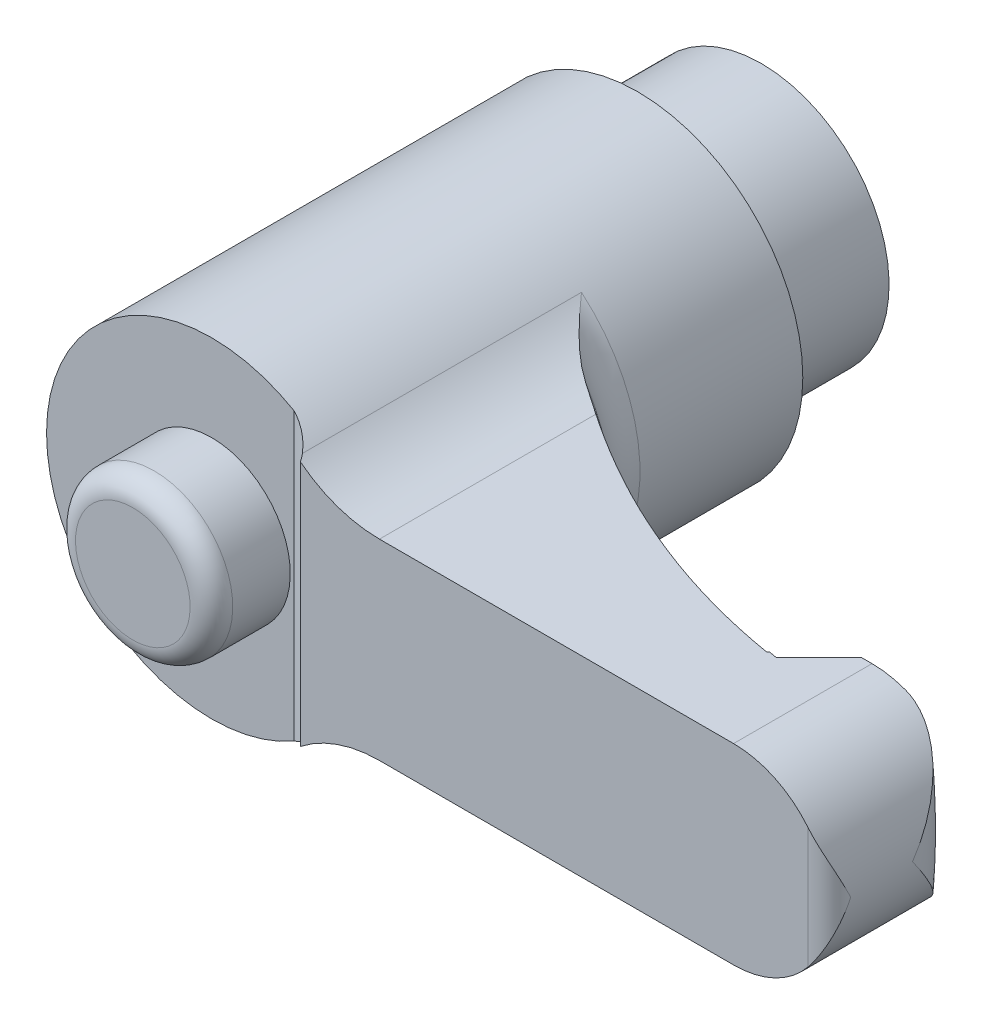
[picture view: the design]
ISO-10303-21;
HEADER;
FILE_DESCRIPTION(('STEP AP214'),'2;1');
FILE_NAME('part.step','',(''),(''),'','','');
FILE_SCHEMA(('AUTOMOTIVE_DESIGN { 1 0 10303 214 1 1 1 1 }'));
ENDSEC;
DATA;
#1=APPLICATION_CONTEXT('core data for automotive mechanical design processes');
#2=APPLICATION_PROTOCOL_DEFINITION('international standard','automotive_design',2000,#1);
#3=PRODUCT_CONTEXT('',#1,'mechanical');
#4=PRODUCT('Part','Part','',(#3));
#5=PRODUCT_RELATED_PRODUCT_CATEGORY('part','',(#4));
#6=PRODUCT_DEFINITION_FORMATION('','',#4);
#7=PRODUCT_DEFINITION_CONTEXT('part definition',#1,'design');
#8=PRODUCT_DEFINITION('design','',#6,#7);
#9=PRODUCT_DEFINITION_SHAPE('','',#8);
#10=(LENGTH_UNIT() NAMED_UNIT(*) SI_UNIT(.MILLI.,.METRE.));
#11=(NAMED_UNIT(*) PLANE_ANGLE_UNIT() SI_UNIT($,.RADIAN.));
#12=(NAMED_UNIT(*) SI_UNIT($,.STERADIAN.) SOLID_ANGLE_UNIT());
#13=UNCERTAINTY_MEASURE_WITH_UNIT(LENGTH_MEASURE(1.E-05),#10,'distance_accuracy_value','');
#14=(GEOMETRIC_REPRESENTATION_CONTEXT(3) GLOBAL_UNCERTAINTY_ASSIGNED_CONTEXT((#13)) GLOBAL_UNIT_ASSIGNED_CONTEXT((#10,
#11,#12)) REPRESENTATION_CONTEXT('',''));
#15=CARTESIAN_POINT('',(0.,0.,0.));
#16=DIRECTION('',(0.,0.,1.));
#17=DIRECTION('',(1.,0.,0.));
#18=AXIS2_PLACEMENT_3D('',#15,#16,#17);
#19=CARTESIAN_POINT('',(4.8,0.,0.));
#20=DIRECTION('',(0.,0.,1.));
#21=DIRECTION('',(0.,-1.,0.));
#22=AXIS2_PLACEMENT_3D('',#19,#20,#21);
#23=PLANE('',#22);
#24=CARTESIAN_POINT('',(0.,0.,0.));
#25=DIRECTION('',(0.,0.,-1.));
#26=DIRECTION('',(0.,1.,0.));
#27=AXIS2_PLACEMENT_3D('',#24,#25,#26);
#28=CIRCLE('',#27,2.);
#29=CARTESIAN_POINT('',(0.,2.,0.));
#30=VERTEX_POINT('',#29);
#31=EDGE_CURVE('E488',#30,#30,#28,.T.);
#32=ORIENTED_EDGE('',*,*,#31,.F.);
#33=EDGE_LOOP('',(#32));
#34=FACE_BOUND('',#33,.T.);
#35=CARTESIAN_POINT('',(0.,0.,0.));
#36=DIRECTION('',(0.,0.,-1.));
#37=DIRECTION('',(0.,1.,0.));
#38=AXIS2_PLACEMENT_3D('',#35,#36,#37);
#39=CIRCLE('',#38,4.8);
#40=CARTESIAN_POINT('',(0.,4.8,0.));
#41=VERTEX_POINT('',#40);
#42=EDGE_CURVE('E427',#41,#41,#39,.T.);
#43=ORIENTED_EDGE('',*,*,#42,.T.);
#44=EDGE_LOOP('',(#43));
#45=FACE_BOUND('',#44,.T.);
#46=ADVANCED_FACE('F14',(#34,#45),#23,.F.);
#47=CARTESIAN_POINT('',(0.,0.,26.));
#48=DIRECTION('',(0.,0.,-1.));
#49=DIRECTION('',(0.,1.,0.));
#50=AXIS2_PLACEMENT_3D('',#47,#48,#49);
#51=PLANE('',#50);
#52=CARTESIAN_POINT('',(0.,0.,26.));
#53=DIRECTION('',(0.,0.,-1.));
#54=DIRECTION('',(0.,1.,0.));
#55=AXIS2_PLACEMENT_3D('',#52,#53,#54);
#56=CIRCLE('',#55,7.75);
#57=CARTESIAN_POINT('',(3.875,-6.7116968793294,26.));
#58=VERTEX_POINT('',#57);
#59=CARTESIAN_POINT('',(3.875,6.7116968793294,26.));
#60=VERTEX_POINT('',#59);
#61=EDGE_CURVE('E374',#58,#60,#56,.T.);
#62=ORIENTED_EDGE('',*,*,#61,.F.);
#63=DIRECTION('',(0.,1.,0.));
#64=VECTOR('',#63,1.);
#65=CARTESIAN_POINT('',(3.875,-9.,26.));
#66=LINE('',#65,#64);
#67=EDGE_CURVE('E461',#58,#60,#66,.T.);
#68=ORIENTED_EDGE('',*,*,#67,.T.);
#69=EDGE_LOOP('',(#62,#68));
#70=FACE_BOUND('',#69,.T.);
#71=CARTESIAN_POINT('',(0.,0.,26.));
#72=DIRECTION('',(0.,0.,-1.));
#73=DIRECTION('',(0.,1.,0.));
#74=AXIS2_PLACEMENT_3D('',#71,#72,#73);
#75=CIRCLE('',#74,3.69047619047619);
#76=CARTESIAN_POINT('',(0.,3.69047619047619,26.));
#77=VERTEX_POINT('',#76);
#78=EDGE_CURVE('E9',#77,#77,#75,.F.);
#79=ORIENTED_EDGE('',*,*,#78,.F.);
#80=EDGE_LOOP('',(#79));
#81=FACE_BOUND('',#80,.T.);
#82=ADVANCED_FACE('F16',(#70,#81),#51,.F.);
#83=CARTESIAN_POINT('',(25.5,0.,0.));
#84=DIRECTION('',(0.,0.,1.));
#85=DIRECTION('',(0.,-1.,0.));
#86=AXIS2_PLACEMENT_3D('',#83,#84,#85);
#87=CYLINDRICAL_SURFACE('',#86,4.5);
#88=CARTESIAN_POINT('',(30.,0.,23.1));
#89=CARTESIAN_POINT('',(30.0000000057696,-0.00397224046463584,23.0972162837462));
#90=CARTESIAN_POINT('',(29.9999947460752,-0.00794462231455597,23.0944324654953));
#91=CARTESIAN_POINT('',(29.9991779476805,-0.316207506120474,22.8784039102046));
#92=CARTESIAN_POINT('',(29.967472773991,-0.621260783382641,22.6646232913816));
#93=CARTESIAN_POINT('',(29.8729566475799,-1.07288244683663,22.3499400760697));
#94=CARTESIAN_POINT('',(29.8335087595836,-1.2227001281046,22.2458576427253));
#95=CARTESIAN_POINT('',(29.7386099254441,-1.51933949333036,22.0407893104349));
#96=CARTESIAN_POINT('',(29.6831664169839,-1.6661625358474,21.9398019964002));
#97=CARTESIAN_POINT('',(29.5225221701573,-2.0316181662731,21.690355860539));
#98=CARTESIAN_POINT('',(29.4064726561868,-2.24755940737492,21.5447545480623));
#99=CARTESIAN_POINT('',(29.1349908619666,-2.66429651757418,21.2699985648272));
#100=CARTESIAN_POINT('',(28.9796468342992,-2.86512503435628,21.1408080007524));
#101=CARTESIAN_POINT('',(28.6740094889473,-3.19567948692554,20.9378778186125));
#102=CARTESIAN_POINT('',(28.5328529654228,-3.3303385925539,20.8584463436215));
#103=CARTESIAN_POINT('',(28.2285136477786,-3.58389708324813,20.7186599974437));
#104=CARTESIAN_POINT('',(28.0653563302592,-3.70281438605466,20.6582833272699));
#105=CARTESIAN_POINT('',(27.7569268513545,-3.89637158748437,20.5739705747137));
#106=CARTESIAN_POINT('',(27.6155988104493,-3.97499958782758,20.5449430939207));
#107=CARTESIAN_POINT('',(27.3962983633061,-4.08175109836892,20.516319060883));
#108=CARTESIAN_POINT('',(27.3219652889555,-4.11547521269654,20.5092639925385));
#109=CARTESIAN_POINT('',(27.1713145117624,-4.17892025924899,20.5006475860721));
#110=CARTESIAN_POINT('',(27.0949977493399,-4.20864304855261,20.4990836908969));
#111=CARTESIAN_POINT('',(26.940135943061,-4.26413478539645,20.5019689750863));
#112=CARTESIAN_POINT('',(26.8615759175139,-4.28985895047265,20.5064814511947));
#113=CARTESIAN_POINT('',(26.7037978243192,-4.33677756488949,20.5220962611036));
#114=CARTESIAN_POINT('',(26.624580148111,-4.35797453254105,20.5331949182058));
#115=CARTESIAN_POINT('',(26.4663684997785,-4.39576374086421,20.5623470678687));
#116=CARTESIAN_POINT('',(26.3873744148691,-4.41235899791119,20.5803959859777));
#117=CARTESIAN_POINT('',(26.230581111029,-4.44101436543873,20.6236628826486));
#118=CARTESIAN_POINT('',(26.1527814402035,-4.4530762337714,20.6488780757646));
#119=CARTESIAN_POINT('',(25.9747863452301,-4.47604389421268,20.7158088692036));
#120=CARTESIAN_POINT('',(25.8753706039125,-4.48535121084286,20.7602222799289));
#121=CARTESIAN_POINT('',(25.7308199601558,-4.4943380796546,20.836059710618));
#122=CARTESIAN_POINT('',(25.6833620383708,-4.49650441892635,20.8629005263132));
#123=CARTESIAN_POINT('',(25.5902043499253,-4.4993369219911,20.9195771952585));
#124=CARTESIAN_POINT('',(25.5445050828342,-4.50000266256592,20.9494138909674));
#125=CARTESIAN_POINT('',(25.4998,-4.49999999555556,20.980704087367));
#126=B_SPLINE_CURVE_WITH_KNOTS('',3,(#88,#89,#90,#91,#92,#93,#94,#95,#96,#97,#98,#99,#100,#101,
#102,#103,#104,#105,#106,#107,#108,#109,#110,#111,#112,#113,#114,#115,#116,#117,#118,#119,#120,
#121,#122,#123,#124,#125),.UNSPECIFIED.,.F.,.F.,(4,2,2,2,2,2,2,2,2,2,2,2,2,2,2,2,2,2,4),(0.,
0.0145521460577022,1.12923174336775,1.68863416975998,2.24777690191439,3.0999476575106,
3.95022123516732,4.58000022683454,5.20905610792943,5.69992949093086,5.94545977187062,
6.19087570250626,6.43886797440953,6.68672193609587,6.93441304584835,7.18200801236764,
7.50864895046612,7.67223429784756,7.83586577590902),.UNSPECIFIED.);
#127=CARTESIAN_POINT('',(27.0737254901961,-4.21584962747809,20.5));
#128=VERTEX_POINT('',#127);
#129=CARTESIAN_POINT('',(30.,0.,23.1));
#130=VERTEX_POINT('',#129);
#131=EDGE_CURVE('E133',#128,#130,#126,.F.);
#132=ORIENTED_EDGE('',*,*,#131,.T.);
#133=CARTESIAN_POINT('',(30.,0.,23.1));
#134=CARTESIAN_POINT('',(30.0000000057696,0.00397224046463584,23.0972162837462));
#135=CARTESIAN_POINT('',(29.9999947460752,0.00794462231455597,23.0944324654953));
#136=CARTESIAN_POINT('',(29.9991779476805,0.316207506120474,22.8784039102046));
#137=CARTESIAN_POINT('',(29.967472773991,0.621260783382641,22.6646232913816));
#138=CARTESIAN_POINT('',(29.8729566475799,1.07288244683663,22.3499400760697));
#139=CARTESIAN_POINT('',(29.8335087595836,1.2227001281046,22.2458576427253));
#140=CARTESIAN_POINT('',(29.7386099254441,1.51933949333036,22.0407893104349));
#141=CARTESIAN_POINT('',(29.6831664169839,1.6661625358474,21.9398019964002));
#142=CARTESIAN_POINT('',(29.5225221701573,2.0316181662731,21.690355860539));
#143=CARTESIAN_POINT('',(29.4064726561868,2.24755940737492,21.5447545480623));
#144=CARTESIAN_POINT('',(29.1349908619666,2.66429651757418,21.2699985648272));
#145=CARTESIAN_POINT('',(28.9796468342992,2.86512503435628,21.1408080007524));
#146=CARTESIAN_POINT('',(28.6740094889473,3.19567948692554,20.9378778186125));
#147=CARTESIAN_POINT('',(28.5328529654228,3.3303385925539,20.8584463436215));
#148=CARTESIAN_POINT('',(28.2285136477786,3.58389708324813,20.7186599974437));
#149=CARTESIAN_POINT('',(28.0653563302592,3.70281438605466,20.6582833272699));
#150=CARTESIAN_POINT('',(27.7569268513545,3.89637158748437,20.5739705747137));
#151=CARTESIAN_POINT('',(27.6155988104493,3.97499958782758,20.5449430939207));
#152=CARTESIAN_POINT('',(27.3962983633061,4.08175109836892,20.516319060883));
#153=CARTESIAN_POINT('',(27.3219652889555,4.11547521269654,20.5092639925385));
#154=CARTESIAN_POINT('',(27.1713145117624,4.17892025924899,20.5006475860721));
#155=CARTESIAN_POINT('',(27.0949977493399,4.20864304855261,20.4990836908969));
#156=CARTESIAN_POINT('',(26.940135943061,4.26413478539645,20.5019689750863));
#157=CARTESIAN_POINT('',(26.8615759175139,4.28985895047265,20.5064814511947));
#158=CARTESIAN_POINT('',(26.7037978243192,4.33677756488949,20.5220962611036));
#159=CARTESIAN_POINT('',(26.624580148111,4.35797453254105,20.5331949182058));
#160=CARTESIAN_POINT('',(26.4663684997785,4.39576374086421,20.5623470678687));
#161=CARTESIAN_POINT('',(26.3873744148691,4.41235899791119,20.5803959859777));
#162=CARTESIAN_POINT('',(26.230581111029,4.44101436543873,20.6236628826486));
#163=CARTESIAN_POINT('',(26.1527814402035,4.4530762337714,20.6488780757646));
#164=CARTESIAN_POINT('',(25.9747863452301,4.47604389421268,20.7158088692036));
#165=CARTESIAN_POINT('',(25.8753706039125,4.48535121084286,20.7602222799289));
#166=CARTESIAN_POINT('',(25.7308199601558,4.4943380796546,20.836059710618));
#167=CARTESIAN_POINT('',(25.6833620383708,4.49650441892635,20.8629005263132));
#168=CARTESIAN_POINT('',(25.5902043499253,4.4993369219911,20.9195771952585));
#169=CARTESIAN_POINT('',(25.5445050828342,4.50000266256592,20.9494138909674));
#170=CARTESIAN_POINT('',(25.4998,4.49999999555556,20.980704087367));
#171=B_SPLINE_CURVE_WITH_KNOTS('',3,(#133,#134,#135,#136,#137,#138,#139,#140,#141,#142,#143,
#144,#145,#146,#147,#148,#149,#150,#151,#152,#153,#154,#155,#156,#157,#158,#159,#160,#161,#162,
#163,#164,#165,#166,#167,#168,#169,#170),.UNSPECIFIED.,.F.,.F.,(4,2,2,2,2,2,2,2,2,2,2,2,2,2,2,2,
2,2,4),(0.,0.0145521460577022,1.12923174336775,1.68863416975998,2.24777690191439,
3.0999476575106,3.95022123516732,4.58000022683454,5.20905610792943,5.69992949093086,
5.94545977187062,6.19087570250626,6.43886797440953,6.68672193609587,6.93441304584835,
7.18200801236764,7.50864895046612,7.67223429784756,7.83586577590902),.UNSPECIFIED.);
#172=CARTESIAN_POINT('',(27.0737254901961,4.21584962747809,20.5));
#173=VERTEX_POINT('',#172);
#174=EDGE_CURVE('E130',#130,#173,#171,.T.);
#175=ORIENTED_EDGE('',*,*,#174,.T.);
#176=CARTESIAN_POINT('',(25.5,0.,20.5));
#177=DIRECTION('',(0.,0.,-1.));
#178=DIRECTION('',(0.,1.,0.));
#179=AXIS2_PLACEMENT_3D('',#176,#177,#178);
#180=CIRCLE('',#179,4.5);
#181=CARTESIAN_POINT('',(25.5,4.5,20.5));
#182=VERTEX_POINT('',#181);
#183=EDGE_CURVE('E399',#173,#182,#180,.F.);
#184=ORIENTED_EDGE('',*,*,#183,.T.);
#185=DIRECTION('',(0.,0.,1.));
#186=VECTOR('',#185,1.);
#187=CARTESIAN_POINT('',(25.5,4.5,0.));
#188=LINE('',#187,#186);
#189=CARTESIAN_POINT('',(25.5,4.5,27.));
#190=VERTEX_POINT('',#189);
#191=EDGE_CURVE('E398',#182,#190,#188,.T.);
#192=ORIENTED_EDGE('',*,*,#191,.T.);
#193=CARTESIAN_POINT('',(25.5,0.,27.));
#194=DIRECTION('',(0.,0.,1.));
#195=DIRECTION('',(0.,-1.,0.));
#196=AXIS2_PLACEMENT_3D('',#193,#194,#195);
#197=CIRCLE('',#196,4.5);
#198=CARTESIAN_POINT('',(29.,2.82842712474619,27.));
#199=VERTEX_POINT('',#198);
#200=EDGE_CURVE('E377',#199,#190,#197,.T.);
#201=ORIENTED_EDGE('',*,*,#200,.F.);
#202=CARTESIAN_POINT('',(29.,2.82842712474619,27.));
#203=CARTESIAN_POINT('',(29.0452569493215,2.77244060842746,26.9999705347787));
#204=CARTESIAN_POINT('',(29.08910814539,2.71541373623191,26.9969310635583));
#205=CARTESIAN_POINT('',(29.1737346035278,2.59976408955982,26.9857221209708));
#206=CARTESIAN_POINT('',(29.2145155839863,2.54114457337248,26.9775624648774));
#207=CARTESIAN_POINT('',(29.2926216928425,2.42301598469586,26.9570723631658));
#208=CARTESIAN_POINT('',(29.3299701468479,2.36351669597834,26.9447732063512));
#209=CARTESIAN_POINT('',(29.4015263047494,2.24343051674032,26.9166544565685));
#210=CARTESIAN_POINT('',(29.4357319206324,2.18284293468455,26.9008325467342));
#211=CARTESIAN_POINT('',(29.5205149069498,2.0242761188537,26.8558925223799));
#212=CARTESIAN_POINT('',(29.5686353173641,1.92562477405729,26.8244847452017));
#213=CARTESIAN_POINT('',(29.6569408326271,1.7267576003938,26.7560098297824));
#214=CARTESIAN_POINT('',(29.6971228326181,1.62654117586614,26.7189404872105));
#215=CARTESIAN_POINT('',(29.769924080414,1.42454335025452,26.6403878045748));
#216=CARTESIAN_POINT('',(29.8025090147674,1.32275698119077,26.5988856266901));
#217=CARTESIAN_POINT('',(29.8600923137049,1.1184186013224,26.5127603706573));
#218=CARTESIAN_POINT('',(29.8850925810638,1.0158667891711,26.4681380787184));
#219=CARTESIAN_POINT('',(29.9373931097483,0.763467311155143,26.3559210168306));
#220=CARTESIAN_POINT('',(29.9605764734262,0.613303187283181,26.2871011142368));
#221=CARTESIAN_POINT('',(29.9916507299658,0.312779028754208,26.1474204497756));
#222=CARTESIAN_POINT('',(29.999578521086,0.162420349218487,26.0765650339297));
#223=CARTESIAN_POINT('',(29.9999945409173,0.00809034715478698,26.0038138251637));
#224=CARTESIAN_POINT('',(29.999999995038,0.00404514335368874,26.0019068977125));
#225=CARTESIAN_POINT('',(30.,0.,26.));
#226=B_SPLINE_CURVE_WITH_KNOTS('',3,(#202,#203,#204,#205,#206,#207,#208,#209,#210,#211,#212,
#213,#214,#215,#216,#217,#218,#219,#220,#221,#222,#223,#224,#225),.UNSPECIFIED.,.F.,.F.,(4,2,2,
2,2,2,2,2,2,2,2,4),(0.,0.215782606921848,0.431152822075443,0.644930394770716,0.858848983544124,
1.20082332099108,1.5429311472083,1.88655545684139,2.23009348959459,2.7297347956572,
3.22816610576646,3.2415825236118),.UNSPECIFIED.);
#227=CARTESIAN_POINT('',(30.,0.,26.));
#228=VERTEX_POINT('',#227);
#229=EDGE_CURVE('E173',#228,#199,#226,.F.);
#230=ORIENTED_EDGE('',*,*,#229,.F.);
#231=CARTESIAN_POINT('',(29.,-2.82842712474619,27.));
#232=CARTESIAN_POINT('',(29.0452569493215,-2.77244060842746,26.9999705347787));
#233=CARTESIAN_POINT('',(29.08910814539,-2.71541373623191,26.9969310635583));
#234=CARTESIAN_POINT('',(29.1737346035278,-2.59976408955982,26.9857221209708));
#235=CARTESIAN_POINT('',(29.2145155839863,-2.54114457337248,26.9775624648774));
#236=CARTESIAN_POINT('',(29.2926216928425,-2.42301598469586,26.9570723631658));
#237=CARTESIAN_POINT('',(29.3299701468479,-2.36351669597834,26.9447732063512));
#238=CARTESIAN_POINT('',(29.4015263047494,-2.24343051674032,26.9166544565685));
#239=CARTESIAN_POINT('',(29.4357319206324,-2.18284293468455,26.9008325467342));
#240=CARTESIAN_POINT('',(29.5205149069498,-2.0242761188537,26.8558925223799));
#241=CARTESIAN_POINT('',(29.5686353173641,-1.92562477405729,26.8244847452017));
#242=CARTESIAN_POINT('',(29.6569408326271,-1.7267576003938,26.7560098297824));
#243=CARTESIAN_POINT('',(29.6971228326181,-1.62654117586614,26.7189404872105));
#244=CARTESIAN_POINT('',(29.769924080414,-1.42454335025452,26.6403878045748));
#245=CARTESIAN_POINT('',(29.8025090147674,-1.32275698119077,26.5988856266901));
#246=CARTESIAN_POINT('',(29.8600923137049,-1.1184186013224,26.5127603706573));
#247=CARTESIAN_POINT('',(29.8850925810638,-1.0158667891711,26.4681380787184));
#248=CARTESIAN_POINT('',(29.9373931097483,-0.763467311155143,26.3559210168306));
#249=CARTESIAN_POINT('',(29.9605764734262,-0.613303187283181,26.2871011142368));
#250=CARTESIAN_POINT('',(29.9916507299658,-0.312779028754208,26.1474204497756));
#251=CARTESIAN_POINT('',(29.999578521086,-0.162420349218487,26.0765650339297));
#252=CARTESIAN_POINT('',(29.9999945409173,-0.00809034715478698,26.0038138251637));
#253=CARTESIAN_POINT('',(29.999999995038,-0.00404514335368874,26.0019068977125));
#254=CARTESIAN_POINT('',(30.,0.,26.));
#255=B_SPLINE_CURVE_WITH_KNOTS('',3,(#231,#232,#233,#234,#235,#236,#237,#238,#239,#240,#241,
#242,#243,#244,#245,#246,#247,#248,#249,#250,#251,#252,#253,#254),.UNSPECIFIED.,.F.,.F.,(4,2,2,
2,2,2,2,2,2,2,2,4),(0.,0.215782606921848,0.431152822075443,0.644930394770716,0.858848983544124,
1.20082332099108,1.5429311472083,1.88655545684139,2.23009348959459,2.7297347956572,
3.22816610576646,3.2415825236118),.UNSPECIFIED.);
#256=CARTESIAN_POINT('',(29.,-2.82842712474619,27.));
#257=VERTEX_POINT('',#256);
#258=EDGE_CURVE('E22',#257,#228,#255,.T.);
#259=ORIENTED_EDGE('',*,*,#258,.F.);
#260=CARTESIAN_POINT('',(25.5,-4.5,27.));
#261=VERTEX_POINT('',#260);
#262=EDGE_CURVE('E383',#261,#257,#197,.T.);
#263=ORIENTED_EDGE('',*,*,#262,.F.);
#264=DIRECTION('',(0.,0.,1.));
#265=VECTOR('',#264,1.);
#266=CARTESIAN_POINT('',(25.5,-4.5,0.));
#267=LINE('',#266,#265);
#268=CARTESIAN_POINT('',(25.5,-4.5,20.5));
#269=VERTEX_POINT('',#268);
#270=EDGE_CURVE('E403',#269,#261,#267,.T.);
#271=ORIENTED_EDGE('',*,*,#270,.F.);
#272=EDGE_CURVE('E140',#269,#128,#180,.F.);
#273=ORIENTED_EDGE('',*,*,#272,.T.);
#274=EDGE_LOOP('',(#132,#175,#184,#192,#201,#230,#259,#263,#271,#273));
#275=FACE_BOUND('',#274,.T.);
#276=ADVANCED_FACE('F138',(#275),#87,.T.);
#277=CARTESIAN_POINT('',(28.072410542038,-9.,-7.06806810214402));
#278=DIRECTION('',(0.,1.,0.));
#279=DIRECTION('',(-1.,0.,0.));
#280=AXIS2_PLACEMENT_3D('',#277,#278,#279);
#281=CYLINDRICAL_SURFACE('',#280,30.);
#282=CARTESIAN_POINT('',(22.457864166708,5.40076351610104,22.4018635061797));
#283=CARTESIAN_POINT('',(22.5328704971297,5.02783315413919,22.4161416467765));
#284=CARTESIAN_POINT('',(22.6003478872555,4.65331694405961,22.4287120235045));
#285=CARTESIAN_POINT('',(22.7199001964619,3.90172149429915,22.4506465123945));
#286=CARTESIAN_POINT('',(22.7719742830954,3.52464211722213,22.4600104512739));
#287=CARTESIAN_POINT('',(22.860391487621,2.76836181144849,22.4757441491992));
#288=CARTESIAN_POINT('',(22.8967259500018,2.38915983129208,22.4821122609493));
#289=CARTESIAN_POINT('',(22.953399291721,1.62955869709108,22.4919810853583));
#290=CARTESIAN_POINT('',(22.9737386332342,1.24915957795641,22.4954818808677));
#291=CARTESIAN_POINT('',(23.0101209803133,0.119914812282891,22.5017516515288));
#292=CARTESIAN_POINT('',(23.0030278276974,-0.62982701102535,22.5005458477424));
#293=CARTESIAN_POINT('',(22.9265280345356,-2.12549757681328,22.487326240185));
#294=CARTESIAN_POINT('',(22.8571649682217,-2.87142861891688,22.4753199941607));
#295=CARTESIAN_POINT('',(22.717445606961,-3.91200869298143,22.450161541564));
#296=CARTESIAN_POINT('',(22.6723784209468,-4.21035002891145,22.4419679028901));
#297=CARTESIAN_POINT('',(22.5724363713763,-4.80637536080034,22.4235048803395));
#298=CARTESIAN_POINT('',(22.5175283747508,-5.10405358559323,22.4132284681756));
#299=CARTESIAN_POINT('',(22.457864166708,-5.40076351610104,22.4018635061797));
#300=B_SPLINE_CURVE_WITH_KNOTS('',3,(#282,#283,#284,#285,#286,#287,#288,#289,#290,#291,#292,
#293,#294,#295,#296,#297,#298,#299),.UNSPECIFIED.,.F.,.F.,(4,2,2,2,2,2,2,2,4),(0.,
1.14192528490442,2.28391227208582,3.4265264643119,4.56910763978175,6.81558260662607,
9.06048679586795,9.96586555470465,10.8743519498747),.UNSPECIFIED.);
#301=CARTESIAN_POINT('',(23.,0.,22.5));
#302=VERTEX_POINT('',#301);
#303=CARTESIAN_POINT('',(22.6238084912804,-4.5,22.4329951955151));
#304=VERTEX_POINT('',#303);
#305=EDGE_CURVE('E136',#302,#304,#300,.T.);
#306=ORIENTED_EDGE('',*,*,#305,.F.);
#307=DIRECTION('',(0.,1.,0.));
#308=VECTOR('',#307,1.);
#309=CARTESIAN_POINT('',(23.,-9.,22.5));
#310=LINE('',#309,#308);
#311=CARTESIAN_POINT('',(23.,-4.5,22.5));
#312=VERTEX_POINT('',#311);
#313=EDGE_CURVE('E467',#312,#302,#310,.T.);
#314=ORIENTED_EDGE('',*,*,#313,.F.);
#315=CARTESIAN_POINT('',(28.072410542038,-4.5,-7.06806810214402));
#316=DIRECTION('',(0.,1.,0.));
#317=DIRECTION('',(-1.,0.,0.));
#318=AXIS2_PLACEMENT_3D('',#315,#316,#317);
#319=CIRCLE('',#318,30.);
#320=EDGE_CURVE('E458',#312,#304,#319,.F.);
#321=ORIENTED_EDGE('',*,*,#320,.T.);
#322=EDGE_LOOP('',(#306,#314,#321));
#323=FACE_BOUND('',#322,.T.);
#324=ADVANCED_FACE('F162',(#323),#281,.F.);
#325=CARTESIAN_POINT('',(27.4,-9.,20.5));
#326=DIRECTION('',(0.,0.,-1.));
#327=DIRECTION('',(0.,1.,0.));
#328=AXIS2_PLACEMENT_3D('',#325,#326,#327);
#329=PLANE('',#328);
#330=ORIENTED_EDGE('',*,*,#183,.F.);
#331=CARTESIAN_POINT('',(0.,0.,20.5));
#332=DIRECTION('',(0.,0.,-1.));
#333=DIRECTION('',(0.,1.,0.));
#334=AXIS2_PLACEMENT_3D('',#331,#332,#333);
#335=CIRCLE('',#334,27.4);
#336=EDGE_CURVE('E37',#173,#128,#335,.T.);
#337=ORIENTED_EDGE('',*,*,#336,.T.);
#338=ORIENTED_EDGE('',*,*,#272,.F.);
#339=DIRECTION('',(-1.,0.,0.));
#340=VECTOR('',#339,1.);
#341=CARTESIAN_POINT('',(25.5,-4.5,20.5));
#342=LINE('',#341,#340);
#343=CARTESIAN_POINT('',(25.,-4.5,20.5));
#344=VERTEX_POINT('',#343);
#345=EDGE_CURVE('E538',#269,#344,#342,.T.);
#346=ORIENTED_EDGE('',*,*,#345,.T.);
#347=DIRECTION('',(0.,1.,0.));
#348=VECTOR('',#347,1.);
#349=CARTESIAN_POINT('',(25.,-9.,20.5));
#350=LINE('',#349,#348);
#351=CARTESIAN_POINT('',(25.,4.5,20.5));
#352=VERTEX_POINT('',#351);
#353=EDGE_CURVE('E454',#344,#352,#350,.T.);
#354=ORIENTED_EDGE('',*,*,#353,.T.);
#355=DIRECTION('',(1.,0.,0.));
#356=VECTOR('',#355,1.);
#357=CARTESIAN_POINT('',(8.87764045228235,4.5,20.5));
#358=LINE('',#357,#356);
#359=EDGE_CURVE('E413',#352,#182,#358,.T.);
#360=ORIENTED_EDGE('',*,*,#359,.T.);
#361=EDGE_LOOP('',(#330,#337,#338,#346,#354,#360));
#362=FACE_BOUND('',#361,.T.);
#363=ADVANCED_FACE('F191',(#362),#329,.T.);
#364=CARTESIAN_POINT('',(0.,0.,27.));
#365=DIRECTION('',(0.,0.,1.));
#366=DIRECTION('',(0.,-1.,0.));
#367=AXIS2_PLACEMENT_3D('',#364,#365,#366);
#368=PLANE('',#367);
#369=CARTESIAN_POINT('',(8.87764045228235,10.5,27.));
#370=DIRECTION('',(0.,0.,1.));
#371=DIRECTION('',(1.,0.,0.));
#372=AXIS2_PLACEMENT_3D('',#369,#370,#371);
#373=CIRCLE('',#372,6.);
#374=CARTESIAN_POINT('',(5.16666666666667,5.78527057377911,27.));
#375=VERTEX_POINT('',#374);
#376=CARTESIAN_POINT('',(8.87764045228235,4.5,27.));
#377=VERTEX_POINT('',#376);
#378=EDGE_CURVE('E408',#375,#377,#373,.T.);
#379=ORIENTED_EDGE('',*,*,#378,.F.);
#380=DIRECTION('',(0.,1.,0.));
#381=VECTOR('',#380,1.);
#382=CARTESIAN_POINT('',(5.16666666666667,-9.,27.));
#383=LINE('',#382,#381);
#384=CARTESIAN_POINT('',(5.16666666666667,-5.78527057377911,27.));
#385=VERTEX_POINT('',#384);
#386=EDGE_CURVE('E447',#385,#375,#383,.T.);
#387=ORIENTED_EDGE('',*,*,#386,.F.);
#388=CARTESIAN_POINT('',(8.87764045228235,-10.5,27.));
#389=DIRECTION('',(0.,0.,1.));
#390=DIRECTION('',(1.,0.,0.));
#391=AXIS2_PLACEMENT_3D('',#388,#389,#390);
#392=CIRCLE('',#391,6.);
#393=CARTESIAN_POINT('',(8.87764045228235,-4.5,27.));
#394=VERTEX_POINT('',#393);
#395=EDGE_CURVE('E411',#394,#385,#392,.T.);
#396=ORIENTED_EDGE('',*,*,#395,.F.);
#397=DIRECTION('',(-1.,0.,0.));
#398=VECTOR('',#397,1.);
#399=CARTESIAN_POINT('',(25.5,-4.5,27.));
#400=LINE('',#399,#398);
#401=EDGE_CURVE('E407',#261,#394,#400,.T.);
#402=ORIENTED_EDGE('',*,*,#401,.F.);
#403=ORIENTED_EDGE('',*,*,#262,.T.);
#404=DIRECTION('',(0.,1.,0.));
#405=VECTOR('',#404,1.);
#406=CARTESIAN_POINT('',(29.,-9.,27.));
#407=LINE('',#406,#405);
#408=EDGE_CURVE('E395',#257,#199,#407,.T.);
#409=ORIENTED_EDGE('',*,*,#408,.T.);
#410=ORIENTED_EDGE('',*,*,#200,.T.);
#411=DIRECTION('',(1.,0.,0.));
#412=VECTOR('',#411,1.);
#413=CARTESIAN_POINT('',(8.87764045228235,4.5,27.));
#414=LINE('',#413,#412);
#415=EDGE_CURVE('E394',#377,#190,#414,.T.);
#416=ORIENTED_EDGE('',*,*,#415,.F.);
#417=EDGE_LOOP('',(#379,#387,#396,#402,#403,#409,#410,#416));
#418=FACE_BOUND('',#417,.T.);
#419=ADVANCED_FACE('F238',(#418),#368,.T.);
#420=CARTESIAN_POINT('',(0.,0.,0.));
#421=DIRECTION('',(0.,0.,-1.));
#422=DIRECTION('',(0.,1.,0.));
#423=AXIS2_PLACEMENT_3D('',#420,#421,#422);
#424=CYLINDRICAL_SURFACE('',#423,7.75);
#425=CARTESIAN_POINT('',(0.,0.,13.6426560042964));
#426=DIRECTION('',(0.,0.,-1.));
#427=DIRECTION('',(0.,1.,0.));
#428=AXIS2_PLACEMENT_3D('',#425,#426,#427);
#429=CIRCLE('',#428,7.75);
#430=CARTESIAN_POINT('',(5.00376098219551,5.91818181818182,13.6426560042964));
#431=VERTEX_POINT('',#430);
#432=CARTESIAN_POINT('',(5.00376098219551,-5.91818181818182,13.6426560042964));
#433=VERTEX_POINT('',#432);
#434=EDGE_CURVE('E368',#431,#433,#429,.T.);
#435=ORIENTED_EDGE('',*,*,#434,.T.);
#436=DIRECTION('',(0.,0.,1.));
#437=VECTOR('',#436,1.);
#438=CARTESIAN_POINT('',(5.00376098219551,-5.91818181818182,0.));
#439=LINE('',#438,#437);
#440=CARTESIAN_POINT('',(5.00376098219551,-5.91818181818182,26.7442638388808));
#441=VERTEX_POINT('',#440);
#442=EDGE_CURVE('E419',#433,#441,#439,.T.);
#443=ORIENTED_EDGE('',*,*,#442,.T.);
#444=CARTESIAN_POINT('',(3.875,-6.7116968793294,26.));
#445=CARTESIAN_POINT('',(3.9487248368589,-6.66914880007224,26.0179048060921));
#446=CARTESIAN_POINT('',(4.02097408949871,-6.62579988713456,26.039874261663));
#447=CARTESIAN_POINT('',(4.16199829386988,-6.53812669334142,26.0915573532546));
#448=CARTESIAN_POINT('',(4.23077434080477,-6.49380272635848,26.1212685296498));
#449=CARTESIAN_POINT('',(4.36202505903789,-6.40634475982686,26.1868862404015));
#450=CARTESIAN_POINT('',(4.42463632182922,-6.36322379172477,26.2225378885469));
#451=CARTESIAN_POINT('',(4.54579687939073,-6.27724013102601,26.3004737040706));
#452=CARTESIAN_POINT('',(4.60434578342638,-6.23437746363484,26.3427585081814));
#453=CARTESIAN_POINT('',(4.71026264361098,-6.1546555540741,26.4283893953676));
#454=CARTESIAN_POINT('',(4.75813291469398,-6.11768751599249,26.4710140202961));
#455=CARTESIAN_POINT('',(4.8500303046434,-6.04509175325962,26.56120031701));
#456=CARTESIAN_POINT('',(4.89405965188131,-6.00946325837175,26.6087590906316));
#457=CARTESIAN_POINT('',(4.97925799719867,-5.9390764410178,26.7103994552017));
#458=CARTESIAN_POINT('',(5.02029084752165,-5.90438218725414,26.7646407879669));
#459=CARTESIAN_POINT('',(5.09738332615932,-5.83796295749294,26.8783962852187));
#460=CARTESIAN_POINT('',(5.13343386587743,-5.80624344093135,26.9379197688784));
#461=CARTESIAN_POINT('',(5.16666666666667,-5.77650894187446,27.));
#462=B_SPLINE_CURVE_WITH_KNOTS('',3,(#444,#445,#446,#447,#448,#449,#450,#451,#452,#453,#454,
#455,#456,#457,#458,#459,#460,#461),.UNSPECIFIED.,.F.,.F.,(4,2,2,2,2,2,2,2,4),(0.,
0.260811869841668,0.521540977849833,0.773092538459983,1.02466826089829,1.24638864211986,
1.4679795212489,1.69664297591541,1.92571819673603),.UNSPECIFIED.);
#463=EDGE_CURVE('E213',#58,#441,#462,.T.);
#464=ORIENTED_EDGE('',*,*,#463,.F.);
#465=ORIENTED_EDGE('',*,*,#61,.T.);
#466=CARTESIAN_POINT('',(5.16666666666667,5.77650894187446,27.));
#467=CARTESIAN_POINT('',(5.13714077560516,5.80292379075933,26.9448365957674));
#468=CARTESIAN_POINT('',(5.1053831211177,5.83091583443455,26.8916890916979));
#469=CARTESIAN_POINT('',(5.03785941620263,5.88934998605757,26.7895453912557));
#470=CARTESIAN_POINT('',(5.00209830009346,5.91978906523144,26.7405442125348));
#471=CARTESIAN_POINT('',(4.92700880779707,5.98243056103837,26.646752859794));
#472=CARTESIAN_POINT('',(4.88768622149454,6.01463008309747,26.6019560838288));
#473=CARTESIAN_POINT('',(4.80573825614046,6.08030777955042,26.5165060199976));
#474=CARTESIAN_POINT('',(4.76311181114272,6.11378636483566,26.4758540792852));
#475=CARTESIAN_POINT('',(4.63114473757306,6.21507952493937,26.3605779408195));
#476=CARTESIAN_POINT('',(4.53728284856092,6.28411879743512,26.2920994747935));
#477=CARTESIAN_POINT('',(4.3393749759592,6.42237347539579,26.1724069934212));
#478=CARTESIAN_POINT('',(4.23533663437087,6.49158871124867,26.1211801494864));
#479=CARTESIAN_POINT('',(4.08621326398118,6.5854168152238,26.0632790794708));
#480=CARTESIAN_POINT('',(4.04469277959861,6.61100425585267,26.0487072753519));
#481=CARTESIAN_POINT('',(3.96061680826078,6.66171281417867,26.0222973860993));
#482=CARTESIAN_POINT('',(3.91806319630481,6.68683464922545,26.0104547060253));
#483=CARTESIAN_POINT('',(3.8750000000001,6.7116968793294,26.));
#484=B_SPLINE_CURVE_WITH_KNOTS('',3,(#466,#467,#468,#469,#470,#471,#472,#473,#474,#475,#476,
#477,#478,#479,#480,#481,#482,#483),.UNSPECIFIED.,.F.,.F.,(4,2,2,2,2,2,2,2,4),(0.,
0.203583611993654,0.406919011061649,0.609929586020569,0.813005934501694,1.21684507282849,
1.62038324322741,1.77301957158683,1.9253970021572),.UNSPECIFIED.);
#485=CARTESIAN_POINT('',(5.0037609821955,5.91818181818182,26.7442638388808));
#486=VERTEX_POINT('',#485);
#487=EDGE_CURVE('E226',#486,#60,#484,.T.);
#488=ORIENTED_EDGE('',*,*,#487,.F.);
#489=DIRECTION('',(0.,0.,1.));
#490=VECTOR('',#489,1.);
#491=CARTESIAN_POINT('',(5.00376098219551,5.91818181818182,0.));
#492=LINE('',#491,#490);
#493=EDGE_CURVE('E425',#431,#486,#492,.T.);
#494=ORIENTED_EDGE('',*,*,#493,.F.);
#495=EDGE_LOOP('',(#435,#443,#464,#465,#488,#494));
#496=FACE_BOUND('',#495,.T.);
#497=CARTESIAN_POINT('',(0.,0.,6.));
#498=DIRECTION('',(0.,0.,-1.));
#499=DIRECTION('',(0.,1.,0.));
#500=AXIS2_PLACEMENT_3D('',#497,#498,#499);
#501=CIRCLE('',#500,7.75);
#502=CARTESIAN_POINT('',(0.,7.75,6.));
#503=VERTEX_POINT('',#502);
#504=EDGE_CURVE('E372',#503,#503,#501,.T.);
#505=ORIENTED_EDGE('',*,*,#504,.F.);
#506=EDGE_LOOP('',(#505));
#507=FACE_BOUND('',#506,.T.);
#508=ADVANCED_FACE('F236',(#496,#507),#424,.T.);
#509=CARTESIAN_POINT('',(8.87764045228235,10.5,0.));
#510=DIRECTION('',(0.,0.,1.));
#511=DIRECTION('',(0.,-1.,0.));
#512=AXIS2_PLACEMENT_3D('',#509,#510,#511);
#513=CYLINDRICAL_SURFACE('',#512,6.);
#514=DIRECTION('',(0.,0.,1.));
#515=VECTOR('',#514,1.);
#516=CARTESIAN_POINT('',(8.87764045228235,4.5,0.));
#517=LINE('',#516,#515);
#518=CARTESIAN_POINT('',(8.87764045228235,4.5,16.8419191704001));
#519=VERTEX_POINT('',#518);
#520=EDGE_CURVE('E402',#519,#377,#517,.T.);
#521=ORIENTED_EDGE('',*,*,#520,.F.);
#522=CARTESIAN_POINT('',(8.87784045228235,4.50000000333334,16.8420543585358));
#523=CARTESIAN_POINT('',(8.76298675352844,4.50000678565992,16.7644412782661));
#524=CARTESIAN_POINT('',(8.64795886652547,4.50329006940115,16.687069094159));
#525=CARTESIAN_POINT('',(8.41786670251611,4.51653249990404,16.5336144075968));
#526=CARTESIAN_POINT('',(8.30280331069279,4.52647413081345,16.457529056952));
#527=CARTESIAN_POINT('',(8.07233993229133,4.55315590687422,16.3070362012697));
#528=CARTESIAN_POINT('',(7.95693991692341,4.56989665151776,16.2326288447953));
#529=CARTESIAN_POINT('',(7.72548993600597,4.61048878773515,16.0861329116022));
#530=CARTESIAN_POINT('',(7.60943905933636,4.63435875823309,16.0140509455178));
#531=CARTESIAN_POINT('',(7.49320434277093,4.66190641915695,15.9436475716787));
#532=B_SPLINE_CURVE_WITH_KNOTS('',3,(#522,#523,#524,#525,#526,#527,#528,#529,#530,#531),
.UNSPECIFIED.,.F.,.F.,(4,2,2,2,4),(0.,0.415830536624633,0.830571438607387,1.24534891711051,
1.66121688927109),.UNSPECIFIED.);
#533=CARTESIAN_POINT('',(7.49353468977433,4.66182809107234,15.9438475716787));
#534=VERTEX_POINT('',#533);
#535=EDGE_CURVE('E252',#519,#534,#532,.T.);
#536=ORIENTED_EDGE('',*,*,#535,.T.);
#537=CARTESIAN_POINT('',(7.49386505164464,4.66174977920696,15.9440475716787));
#538=CARTESIAN_POINT('',(7.41534599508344,4.68036361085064,15.8965108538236));
#539=CARTESIAN_POINT('',(7.33813459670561,4.70033346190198,15.8474028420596));
#540=CARTESIAN_POINT('',(7.18628313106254,4.74278447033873,15.7464454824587));
#541=CARTESIAN_POINT('',(7.11164195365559,4.76526452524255,15.694597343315));
#542=CARTESIAN_POINT('',(6.89171782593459,4.83609524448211,15.5357042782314));
#543=CARTESIAN_POINT('',(6.75010221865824,4.88791699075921,15.4251060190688));
#544=CARTESIAN_POINT('',(6.47674906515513,4.99932791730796,15.1976148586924));
#545=CARTESIAN_POINT('',(6.34496293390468,5.05887426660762,15.0807586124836));
#546=CARTESIAN_POINT('',(6.08952700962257,5.18523508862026,14.8421034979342));
#547=CARTESIAN_POINT('',(5.96588083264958,5.25205275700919,14.7203024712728));
#548=CARTESIAN_POINT('',(5.6959472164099,5.41010140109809,14.4425118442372));
#549=CARTESIAN_POINT('',(5.55174299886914,5.50325599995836,14.2855983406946));
#550=CARTESIAN_POINT('',(5.27355500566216,5.70004368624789,13.9693256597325));
#551=CARTESIAN_POINT('',(5.13957057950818,5.80367610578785,13.8099666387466));
#552=CARTESIAN_POINT('',(5.00807252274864,5.91453907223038,13.6479722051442));
#553=CARTESIAN_POINT('',(5.00591610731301,5.91635969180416,13.6453140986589));
#554=CARTESIAN_POINT('',(5.00376098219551,5.91818181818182,13.6426560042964));
#555=B_SPLINE_CURVE_WITH_KNOTS('',3,(#537,#538,#539,#540,#541,#542,#543,#544,#545,#546,#547,
#548,#549,#550,#551,#552,#553,#554),.UNSPECIFIED.,.F.,.F.,(4,2,2,2,2,2,2,2,4),(0.,
0.280888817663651,0.561654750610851,1.12199628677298,1.67935400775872,2.2369576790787,
2.93418472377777,3.63136735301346,3.6429980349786),.UNSPECIFIED.);
#556=EDGE_CURVE('E243',#534,#431,#555,.T.);
#557=ORIENTED_EDGE('',*,*,#556,.T.);
#558=ORIENTED_EDGE('',*,*,#493,.T.);
#559=CARTESIAN_POINT('',(5.16666666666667,5.78527057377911,27.));
#560=CARTESIAN_POINT('',(5.1544362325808,5.79489712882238,26.9771411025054));
#561=CARTESIAN_POINT('',(5.14182657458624,5.80489933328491,26.9546446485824));
#562=CARTESIAN_POINT('',(5.11593353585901,5.82561925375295,26.910451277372));
#563=CARTESIAN_POINT('',(5.10265156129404,5.83633549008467,26.8887528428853));
#564=CARTESIAN_POINT('',(5.07544919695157,5.85848632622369,26.8461383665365));
#565=CARTESIAN_POINT('',(5.06152881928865,5.86992091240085,26.8252223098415));
#566=CARTESIAN_POINT('',(5.03308032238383,5.89351543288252,26.784152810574));
#567=CARTESIAN_POINT('',(5.0185510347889,5.90567678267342,26.7640009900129));
#568=CARTESIAN_POINT('',(5.0037609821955,5.91818181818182,26.7442638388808));
#569=B_SPLINE_CURVE_WITH_KNOTS('',3,(#559,#560,#561,#562,#563,#564,#565,#566,#567,#568),
.UNSPECIFIED.,.F.,.F.,(4,2,2,2,4),(0.,0.0829550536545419,0.165743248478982,0.248529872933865,
0.331483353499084),.UNSPECIFIED.);
#570=EDGE_CURVE('E220',#375,#486,#569,.T.);
#571=ORIENTED_EDGE('',*,*,#570,.F.);
#572=ORIENTED_EDGE('',*,*,#378,.T.);
#573=EDGE_LOOP('',(#521,#536,#557,#558,#571,#572));
#574=FACE_BOUND('',#573,.T.);
#575=ADVANCED_FACE('F232',(#574),#513,.F.);
#576=CARTESIAN_POINT('',(8.87764045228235,4.5,0.));
#577=DIRECTION('',(0.,-1.,0.));
#578=DIRECTION('',(1.,0.,0.));
#579=AXIS2_PLACEMENT_3D('',#576,#577,#578);
#580=PLANE('',#579);
#581=CARTESIAN_POINT('',(28.072410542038,4.5,-7.06806810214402));
#582=DIRECTION('',(0.,-1.,0.));
#583=DIRECTION('',(1.,0.,0.));
#584=AXIS2_PLACEMENT_3D('',#581,#582,#583);
#585=CIRCLE('',#584,30.);
#586=CARTESIAN_POINT('',(22.6238084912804,4.5,22.432995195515));
#587=VERTEX_POINT('',#586);
#588=CARTESIAN_POINT('',(23.,4.5,22.5));
#589=VERTEX_POINT('',#588);
#590=EDGE_CURVE('E455',#587,#589,#585,.F.);
#591=ORIENTED_EDGE('',*,*,#590,.F.);
#592=CARTESIAN_POINT('',(44.3300735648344,4.5,0.942111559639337));
#593=CARTESIAN_POINT('',(43.4547012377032,4.5,1.81300466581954));
#594=CARTESIAN_POINT('',(42.5792011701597,4.5,2.68376940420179));
#595=CARTESIAN_POINT('',(40.8278840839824,4.5,4.42498033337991));
#596=CARTESIAN_POINT('',(39.9520670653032,4.5,5.29542652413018));
#597=CARTESIAN_POINT('',(37.3240501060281,4.5,7.90619283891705));
#598=CARTESIAN_POINT('',(35.5712829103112,4.5,9.64594205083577));
#599=CARTESIAN_POINT('',(32.0635642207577,4.5,13.1230346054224));
#600=CARTESIAN_POINT('',(30.3086128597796,4.5,14.8603780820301));
#601=CARTESIAN_POINT('',(27.6733297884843,4.5,17.4635089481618));
#602=CARTESIAN_POINT('',(26.7944244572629,4.5,18.3307401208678));
#603=CARTESIAN_POINT('',(25.0353323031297,4.5,20.0639019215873));
#604=CARTESIAN_POINT('',(24.155145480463,4.5,20.9298325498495));
#605=CARTESIAN_POINT('',(22.3129521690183,4.5,22.7385304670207));
#606=CARTESIAN_POINT('',(21.3507796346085,4.5,23.6811286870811));
#607=CARTESIAN_POINT('',(19.4234130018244,4.5,25.5632155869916));
#608=CARTESIAN_POINT('',(18.4582189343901,4.5,26.5027042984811));
#609=CARTESIAN_POINT('',(17.0068469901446,4.5,27.9082821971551));
#610=CARTESIAN_POINT('',(16.5224491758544,4.5,28.3762088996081));
#611=CARTESIAN_POINT('',(15.5521170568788,4.5,29.3104634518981));
#612=CARTESIAN_POINT('',(15.0661827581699,4.5,29.7767913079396));
#613=CARTESIAN_POINT('',(14.0922926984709,4.5,30.7073654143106));
#614=CARTESIAN_POINT('',(13.6043368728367,4.5,31.1716115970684));
#615=CARTESIAN_POINT('',(12.8703741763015,4.5,31.8658425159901));
#616=CARTESIAN_POINT('',(12.625380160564,4.5,32.0968979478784));
#617=CARTESIAN_POINT('',(12.1345901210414,4.5,32.5581570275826));
#618=CARTESIAN_POINT('',(11.8887940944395,4.5,32.7883606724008));
#619=CARTESIAN_POINT('',(11.6425345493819,4.5,33.0180686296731));
#620=B_SPLINE_CURVE_WITH_KNOTS('',3,(#592,#593,#594,#595,#596,#597,#598,#599,#600,#601,#602,
#603,#604,#605,#606,#607,#608,#609,#610,#611,#612,#613,#614,#615,#616,#617,#618,#619),
.UNSPECIFIED.,.F.,.F.,(4,2,2,2,2,2,2,2,2,2,2,2,2,4),(0.,3.70440058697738,7.40880170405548,
14.8175982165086,22.225964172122,25.9301609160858,29.6343569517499,33.6751954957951,
37.7159927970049,39.736477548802,41.7569544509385,43.7774964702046,44.7877808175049,
45.7980687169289),.UNSPECIFIED.);
#621=CARTESIAN_POINT('',(22.55548713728,4.5,22.5));
#622=VERTEX_POINT('',#621);
#623=EDGE_CURVE('E298',#587,#622,#620,.T.);
#624=ORIENTED_EDGE('',*,*,#623,.T.);
#625=CARTESIAN_POINT('',(15.4388208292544,4.5,20.4312501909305));
#626=CARTESIAN_POINT('',(14.9382009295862,4.5,20.2216724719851));
#627=CARTESIAN_POINT('',(14.4426076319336,4.5,19.9999912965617));
#628=CARTESIAN_POINT('',(13.4622769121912,4.5,19.5336725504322));
#629=CARTESIAN_POINT('',(12.9775414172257,4.5,19.2890309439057));
#630=CARTESIAN_POINT('',(12.0194633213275,4.5,18.778303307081));
#631=CARTESIAN_POINT('',(11.5461217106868,4.5,18.5122154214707));
#632=CARTESIAN_POINT('',(10.6110367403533,4.5,17.9604954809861));
#633=CARTESIAN_POINT('',(10.1492927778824,4.5,17.6748644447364));
#634=CARTESIAN_POINT('',(9.23133715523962,4.5,17.0827723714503));
#635=CARTESIAN_POINT('',(8.77526312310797,4.5,16.776098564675));
#636=CARTESIAN_POINT('',(8.09865121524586,4.5,16.3053789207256));
#637=CARTESIAN_POINT('',(7.87435773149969,4.5,16.1466830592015));
#638=CARTESIAN_POINT('',(7.42793360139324,4.5,15.826278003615));
#639=CARTESIAN_POINT('',(7.20580294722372,4.5,15.6645688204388));
#640=CARTESIAN_POINT('',(6.76333109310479,4.5,15.3388557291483));
#641=CARTESIAN_POINT('',(6.54298941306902,4.5,15.1748524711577));
#642=CARTESIAN_POINT('',(6.10341304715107,4.5,14.8453678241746));
#643=CARTESIAN_POINT('',(5.88417837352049,4.5,14.6798864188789));
#644=CARTESIAN_POINT('',(5.44597621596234,4.5,14.3486019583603));
#645=CARTESIAN_POINT('',(5.22700871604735,4.5,14.1827989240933));
#646=CARTESIAN_POINT('',(4.7881475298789,4.5,13.8524268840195));
#647=CARTESIAN_POINT('',(4.56825387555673,4.5,13.6878578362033));
#648=CARTESIAN_POINT('',(4.22599707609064,4.5,13.4359606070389));
#649=CARTESIAN_POINT('',(4.10454867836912,4.5,13.3473935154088));
#650=CARTESIAN_POINT('',(3.86050375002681,4.5,13.1718439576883));
#651=CARTESIAN_POINT('',(3.73790719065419,4.5,13.0848615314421));
#652=CARTESIAN_POINT('',(3.49095051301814,4.5,12.9129975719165));
#653=CARTESIAN_POINT('',(3.36658787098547,4.5,12.8281196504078));
#654=CARTESIAN_POINT('',(3.11579592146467,4.5,12.661467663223));
#655=CARTESIAN_POINT('',(2.98936669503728,4.5,12.5796934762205));
#656=CARTESIAN_POINT('',(2.73559541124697,4.5,12.421447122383));
#657=CARTESIAN_POINT('',(2.60828909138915,4.5,12.3449180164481));
#658=CARTESIAN_POINT('',(2.35045679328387,4.5,12.1973627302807));
#659=CARTESIAN_POINT('',(2.21993005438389,4.5,12.1263378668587));
#660=CARTESIAN_POINT('',(1.95547938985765,4.5,11.9918684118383));
#661=CARTESIAN_POINT('',(1.82156674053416,4.5,11.9284018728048));
#662=CARTESIAN_POINT('',(1.54956725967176,4.5,11.811188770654));
#663=CARTESIAN_POINT('',(1.41148300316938,4.5,11.7574363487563));
#664=CARTESIAN_POINT('',(1.16760292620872,4.5,11.6748301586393));
#665=CARTESIAN_POINT('',(1.06277320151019,4.5,11.6431384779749));
#666=CARTESIAN_POINT('',(0.850970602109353,4.5,11.5877982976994));
#667=CARTESIAN_POINT('',(0.743997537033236,4.5,11.5641505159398));
#668=CARTESIAN_POINT('',(0.528623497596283,4.5,11.5260430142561));
#669=CARTESIAN_POINT('',(0.420225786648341,4.5,11.5115651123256));
#670=CARTESIAN_POINT('',(0.202558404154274,4.5,11.4925018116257));
#671=CARTESIAN_POINT('',(0.0932888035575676,4.5,11.4879156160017));
#672=CARTESIAN_POINT('',(-0.125523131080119,4.5,11.4889012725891));
#673=CARTESIAN_POINT('',(-0.235065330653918,4.5,11.494502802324));
#674=CARTESIAN_POINT('',(-0.453184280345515,4.5,11.5155971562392));
#675=CARTESIAN_POINT('',(-0.561760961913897,4.5,11.5310906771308));
#676=CARTESIAN_POINT('',(-0.777434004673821,4.5,11.5711835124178));
#677=CARTESIAN_POINT('',(-0.884526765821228,4.5,11.5958019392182));
#678=CARTESIAN_POINT('',(-1.09652638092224,4.5,11.653010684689));
#679=CARTESIAN_POINT('',(-1.20143316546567,4.5,11.6856012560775));
#680=CARTESIAN_POINT('',(-1.54299128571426,4.5,11.8040046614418));
#681=CARTESIAN_POINT('',(-1.77469278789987,4.5,11.9041680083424));
#682=CARTESIAN_POINT('',(-2.11370642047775,4.5,12.0712278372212));
#683=CARTESIAN_POINT('',(-2.22542247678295,4.5,12.1298009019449));
#684=CARTESIAN_POINT('',(-2.4464125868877,4.5,12.2514053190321));
#685=CARTESIAN_POINT('',(-2.55568698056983,4.5,12.314436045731));
#686=CARTESIAN_POINT('',(-2.77325410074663,4.5,12.4446206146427));
#687=CARTESIAN_POINT('',(-2.88152520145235,4.5,12.5118101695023));
#688=CARTESIAN_POINT('',(-3.09631836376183,4.5,12.648928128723));
#689=CARTESIAN_POINT('',(-3.20284038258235,4.5,12.7188565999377));
#690=CARTESIAN_POINT('',(-3.41436916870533,4.5,12.8607497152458));
#691=CARTESIAN_POINT('',(-3.51937725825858,4.5,12.9327123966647));
#692=CARTESIAN_POINT('',(-3.72827441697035,4.5,13.0782322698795));
#693=CARTESIAN_POINT('',(-3.83216352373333,4.5,13.1517894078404));
#694=CARTESIAN_POINT('',(-4.05439859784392,4.5,13.3110694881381));
#695=CARTESIAN_POINT('',(-4.17260856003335,4.5,13.3969817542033));
#696=CARTESIAN_POINT('',(-4.4082339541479,4.5,13.5698902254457));
#697=CARTESIAN_POINT('',(-4.52564937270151,4.5,13.6568864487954));
#698=CARTESIAN_POINT('',(-4.87714945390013,4.5,13.9189069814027));
#699=CARTESIAN_POINT('',(-5.11047154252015,4.5,14.094951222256));
#700=CARTESIAN_POINT('',(-5.57685056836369,4.5,14.4474717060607));
#701=CARTESIAN_POINT('',(-5.80990745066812,4.5,14.6239480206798));
#702=CARTESIAN_POINT('',(-6.27690523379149,4.5,14.9757283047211));
#703=CARTESIAN_POINT('',(-6.51084612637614,4.5,15.1510322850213));
#704=CARTESIAN_POINT('',(-6.98047432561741,4.5,15.4993223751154));
#705=CARTESIAN_POINT('',(-7.21616173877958,4.5,15.6723083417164));
#706=CARTESIAN_POINT('',(-7.68986343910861,4.5,16.0150746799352));
#707=CARTESIAN_POINT('',(-7.92787774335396,4.5,16.1848550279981));
#708=CARTESIAN_POINT('',(-8.40663111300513,4.5,16.5205040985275));
#709=CARTESIAN_POINT('',(-8.64736999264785,4.5,16.6863730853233));
#710=CARTESIAN_POINT('',(-9.13186171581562,4.5,17.0136492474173));
#711=CARTESIAN_POINT('',(-9.37561458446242,4.5,17.1750563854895));
#712=CARTESIAN_POINT('',(-10.1060893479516,4.5,17.6482368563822));
#713=CARTESIAN_POINT('',(-10.5975021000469,4.5,17.952835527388));
#714=CARTESIAN_POINT('',(-11.5934664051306,4.5,18.5398125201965));
#715=CARTESIAN_POINT('',(-12.0980184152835,4.5,18.8221900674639));
#716=CARTESIAN_POINT('',(-13.1203636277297,4.5,19.362665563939));
#717=CARTESIAN_POINT('',(-13.6381640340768,4.5,19.6207499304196));
#718=CARTESIAN_POINT('',(-14.6860430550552,4.5,20.11066531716));
#719=CARTESIAN_POINT('',(-15.2161220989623,4.5,20.3424954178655));
#720=CARTESIAN_POINT('',(-16.5720374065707,4.5,20.8941289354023));
#721=CARTESIAN_POINT('',(-17.4055454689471,4.5,21.1953302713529));
#722=CARTESIAN_POINT('',(-19.0940463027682,4.5,21.7283556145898));
#723=CARTESIAN_POINT('',(-19.9490297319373,4.5,21.960209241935));
#724=CARTESIAN_POINT('',(-21.6811099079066,4.5,22.3529309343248));
#725=CARTESIAN_POINT('',(-22.5583149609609,4.5,22.5133231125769));
#726=CARTESIAN_POINT('',(-24.3233745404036,4.5,22.7586307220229));
#727=CARTESIAN_POINT('',(-25.2112306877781,4.5,22.8435345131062));
#728=CARTESIAN_POINT('',(-26.9908314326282,4.5,22.9363918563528));
#729=CARTESIAN_POINT('',(-27.8825753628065,4.5,22.9443581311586));
#730=CARTESIAN_POINT('',(-29.663358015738,4.5,22.8827217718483));
#731=CARTESIAN_POINT('',(-30.5523968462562,4.5,22.8131222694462));
#732=CARTESIAN_POINT('',(-32.31901432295,4.5,22.5966903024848));
#733=CARTESIAN_POINT('',(-33.1966141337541,4.5,22.4500307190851));
#734=CARTESIAN_POINT('',(-34.935590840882,4.5,22.080370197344));
#735=CARTESIAN_POINT('',(-35.796967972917,4.5,21.8573703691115));
#736=CARTESIAN_POINT('',(-37.4685359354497,4.5,21.3451591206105));
#737=CARTESIAN_POINT('',(-38.2794766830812,4.5,21.0583920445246));
#738=CARTESIAN_POINT('',(-39.873960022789,4.5,20.4167921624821));
#739=CARTESIAN_POINT('',(-40.6575033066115,4.5,20.0619610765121));
#740=CARTESIAN_POINT('',(-42.1918635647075,4.5,19.2864593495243));
#741=CARTESIAN_POINT('',(-42.9426616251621,4.5,18.8657512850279));
#742=CARTESIAN_POINT('',(-44.4054978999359,4.5,17.9616153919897));
#743=CARTESIAN_POINT('',(-45.1175362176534,4.5,17.4781877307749));
#744=CARTESIAN_POINT('',(-46.4882343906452,4.5,16.4590216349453));
#745=CARTESIAN_POINT('',(-47.1474852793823,4.5,15.9240778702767));
#746=CARTESIAN_POINT('',(-48.4183395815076,4.5,14.8003122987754));
#747=CARTESIAN_POINT('',(-49.0299435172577,4.5,14.2114910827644));
#748=CARTESIAN_POINT('',(-50.2009517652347,4.5,12.9842748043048));
#749=CARTESIAN_POINT('',(-50.7603665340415,4.5,12.3458897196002));
#750=CARTESIAN_POINT('',(-51.8230723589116,4.5,11.0239977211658));
#751=CARTESIAN_POINT('',(-52.3263634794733,4.5,10.3404908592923));
#752=CARTESIAN_POINT('',(-53.2706922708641,4.5,8.93692421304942));
#753=CARTESIAN_POINT('',(-53.7120407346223,4.5,8.21707350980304));
#754=CARTESIAN_POINT('',(-54.532396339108,4.5,6.74268654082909));
#755=CARTESIAN_POINT('',(-54.9114037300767,4.5,5.98815041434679));
#756=CARTESIAN_POINT('',(-55.6043575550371,4.5,4.44974284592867));
#757=CARTESIAN_POINT('',(-55.9183019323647,4.5,3.66587047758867));
#758=CARTESIAN_POINT('',(-56.478850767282,4.5,2.07440645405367));
#759=CARTESIAN_POINT('',(-56.7254552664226,4.5,1.26681481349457));
#760=CARTESIAN_POINT('',(-57.14904744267,4.5,-0.364399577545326));
#761=CARTESIAN_POINT('',(-57.3261971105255,4.5,-1.18798026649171));
#762=CARTESIAN_POINT('',(-57.6104293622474,4.5,-2.84714412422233));
#763=CARTESIAN_POINT('',(-57.7175120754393,4.5,-3.68272727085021));
#764=CARTESIAN_POINT('',(-57.8608403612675,4.5,-5.35993452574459));
#765=CARTESIAN_POINT('',(-57.8970869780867,4.5,-6.20155854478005));
#766=CARTESIAN_POINT('',(-57.8984858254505,4.5,-7.8848657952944));
#767=CARTESIAN_POINT('',(-57.8636380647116,4.5,-8.72654902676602));
#768=CARTESIAN_POINT('',(-57.7231579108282,4.5,-10.4032722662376));
#769=CARTESIAN_POINT('',(-57.6175852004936,4.5,-11.2383172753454));
#770=CARTESIAN_POINT('',(-57.3364725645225,4.5,-12.8965453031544));
#771=CARTESIAN_POINT('',(-57.1609326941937,4.5,-13.7197283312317));
#772=CARTESIAN_POINT('',(-56.7411440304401,4.5,-15.348385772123));
#773=CARTESIAN_POINT('',(-56.4968951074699,4.5,-16.1538601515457));
#774=CARTESIAN_POINT('',(-55.9414392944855,4.5,-17.7413808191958));
#775=CARTESIAN_POINT('',(-55.6302323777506,4.5,-18.5234270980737));
#776=CARTESIAN_POINT('',(-54.9430163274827,4.5,-20.0587116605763));
#777=CARTESIAN_POINT('',(-54.5669932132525,4.5,-20.8119436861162));
#778=CARTESIAN_POINT('',(-53.7528854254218,4.5,-22.28408588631));
#779=CARTESIAN_POINT('',(-53.3148007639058,4.5,-23.0029960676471));
#780=CARTESIAN_POINT('',(-52.3797121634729,4.5,-24.4014049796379));
#781=CARTESIAN_POINT('',(-51.8827089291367,4.5,-25.0809041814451));
#782=CARTESIAN_POINT('',(-50.8333343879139,4.5,-26.3957112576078));
#783=CARTESIAN_POINT('',(-50.2809630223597,4.5,-27.0310190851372));
#784=CARTESIAN_POINT('',(-49.1240210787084,4.5,-28.2538041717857));
#785=CARTESIAN_POINT('',(-48.519381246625,4.5,-28.841215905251));
#786=CARTESIAN_POINT('',(-47.2628697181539,4.5,-29.9631382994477));
#787=CARTESIAN_POINT('',(-46.6109980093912,4.5,-30.4976489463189));
#788=CARTESIAN_POINT('',(-45.2646445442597,4.5,-31.5100756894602));
#789=CARTESIAN_POINT('',(-44.5701605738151,4.5,-31.9879888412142));
#790=CARTESIAN_POINT('',(-43.1435639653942,4.5,-32.8838941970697));
#791=CARTESIAN_POINT('',(-42.4114512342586,4.5,-33.3018862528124));
#792=CARTESIAN_POINT('',(-40.912331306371,4.5,-34.0763837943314));
#793=CARTESIAN_POINT('',(-40.145216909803,4.5,-34.4326817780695));
#794=CARTESIAN_POINT('',(-38.5838228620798,4.5,-35.0797120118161));
#795=CARTESIAN_POINT('',(-37.7895432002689,4.5,-35.3704442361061));
#796=CARTESIAN_POINT('',(-36.1796169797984,4.5,-35.884414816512));
#797=CARTESIAN_POINT('',(-35.3639746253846,4.5,-36.1076663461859));
#798=CARTESIAN_POINT('',(-33.7169153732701,4.5,-36.485403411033));
#799=CARTESIAN_POINT('',(-32.8854983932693,4.5,-36.6398885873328));
#800=CARTESIAN_POINT('',(-31.2068509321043,4.5,-36.8801373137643));
#801=CARTESIAN_POINT('',(-30.3595503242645,4.5,-36.9654093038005));
#802=CARTESIAN_POINT('',(-28.6606960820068,4.5,-37.0651578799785));
#803=CARTESIAN_POINT('',(-27.8091424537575,4.5,-37.0796345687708));
#804=CARTESIAN_POINT('',(-26.5330536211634,4.5,-37.0485559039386));
#805=CARTESIAN_POINT('',(-26.107715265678,4.5,-37.0293778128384));
#806=CARTESIAN_POINT('',(-25.2581880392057,4.5,-36.9735158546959));
#807=CARTESIAN_POINT('',(-24.8339991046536,4.5,-36.9368329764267));
#808=CARTESIAN_POINT('',(-23.9875137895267,4.5,-36.8461059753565));
#809=CARTESIAN_POINT('',(-23.5652172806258,4.5,-36.7920630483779));
#810=CARTESIAN_POINT('',(-22.7231096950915,4.5,-36.6668007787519));
#811=CARTESIAN_POINT('',(-22.3032991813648,4.5,-36.5955776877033));
#812=CARTESIAN_POINT('',(-21.0326362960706,4.5,-36.3534077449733));
#813=CARTESIAN_POINT('',(-20.1867400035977,4.5,-36.1556925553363));
#814=CARTESIAN_POINT('',(-18.5137717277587,4.5,-35.6923115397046));
#815=CARTESIAN_POINT('',(-17.6867009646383,4.5,-35.4266413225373));
#816=CARTESIAN_POINT('',(-16.4648122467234,4.5,-34.9802120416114));
#817=CARTESIAN_POINT('',(-16.0610185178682,4.5,-34.8235901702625));
#818=CARTESIAN_POINT('',(-15.2598672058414,4.5,-34.494886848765));
#819=CARTESIAN_POINT('',(-14.8625080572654,4.5,-34.3228092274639));
#820=CARTESIAN_POINT('',(-14.0745563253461,4.5,-33.9637665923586));
#821=CARTESIAN_POINT('',(-13.6839641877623,4.5,-33.7768006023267));
#822=CARTESIAN_POINT('',(-12.909871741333,4.5,-33.3886824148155));
#823=CARTESIAN_POINT('',(-12.5263717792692,4.5,-33.1875295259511));
#824=CARTESIAN_POINT('',(-11.8207248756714,4.5,-32.801439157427));
#825=CARTESIAN_POINT('',(-11.4976102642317,4.5,-32.6182650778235));
#826=CARTESIAN_POINT('',(-10.8567820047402,4.5,-32.2426997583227));
#827=CARTESIAN_POINT('',(-10.539068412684,4.5,-32.0503084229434));
#828=CARTESIAN_POINT('',(-9.90902430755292,4.5,-31.6570700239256));
#829=CARTESIAN_POINT('',(-9.59669262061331,4.5,-31.4562248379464));
#830=CARTESIAN_POINT('',(-8.97708038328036,4.5,-31.0468984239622));
#831=CARTESIAN_POINT('',(-8.66979986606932,4.5,-30.838417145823));
#832=CARTESIAN_POINT('',(-8.05909926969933,4.5,-30.414391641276));
#833=CARTESIAN_POINT('',(-7.75568987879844,4.5,-30.1988320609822));
#834=CARTESIAN_POINT('',(-7.15264493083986,4.5,-29.7624945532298));
#835=CARTESIAN_POINT('',(-6.853009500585,4.5,-29.5417164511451));
#836=CARTESIAN_POINT('',(-6.25625428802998,4.5,-29.0968095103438));
#837=CARTESIAN_POINT('',(-5.95913448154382,4.5,-28.8726807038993));
#838=CARTESIAN_POINT('',(-5.51381007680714,4.5,-28.5360257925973));
#839=CARTESIAN_POINT('',(-5.36542874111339,4.5,-28.4237312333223));
#840=CARTESIAN_POINT('',(-5.06841921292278,4.5,-28.199468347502));
#841=CARTESIAN_POINT('',(-4.91979102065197,4.5,-28.0875000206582));
#842=CARTESIAN_POINT('',(-4.6673759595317,4.5,-27.8985569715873));
#843=CARTESIAN_POINT('',(-4.56376685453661,4.5,-27.8213455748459));
#844=CARTESIAN_POINT('',(-4.35603430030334,4.5,-27.6676191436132));
#845=CARTESIAN_POINT('',(-4.25191084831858,4.5,-27.5911041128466));
#846=CARTESIAN_POINT('',(-3.93839628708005,4.5,-27.3629654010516));
#847=CARTESIAN_POINT('',(-3.72792755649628,4.5,-27.2127984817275));
#848=CARTESIAN_POINT('',(-3.40866330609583,4.5,-26.9930527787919));
#849=CARTESIAN_POINT('',(-3.30173041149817,4.5,-26.920774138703));
#850=CARTESIAN_POINT('',(-3.08629576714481,4.5,-26.7785997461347));
#851=CARTESIAN_POINT('',(-2.97779412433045,4.5,-26.7087038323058));
#852=CARTESIAN_POINT('',(-2.75891564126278,4.5,-26.5720402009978));
#853=CARTESIAN_POINT('',(-2.64853991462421,4.5,-26.5052707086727));
#854=CARTESIAN_POINT('',(-2.42546973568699,4.5,-26.3757336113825));
#855=CARTESIAN_POINT('',(-2.31277560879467,4.5,-26.3129654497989));
#856=CARTESIAN_POINT('',(-2.08830306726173,4.5,-26.1944953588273));
#857=CARTESIAN_POINT('',(-1.97661068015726,4.5,-26.1386316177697));
#858=CARTESIAN_POINT('',(-1.75033429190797,4.5,-26.0330124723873));
#859=CARTESIAN_POINT('',(-1.63575004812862,4.5,-25.9832575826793));
#860=CARTESIAN_POINT('',(-1.40370429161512,4.5,-25.8914945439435));
#861=CARTESIAN_POINT('',(-1.28624783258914,4.5,-25.8494737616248));
#862=CARTESIAN_POINT('',(-1.04839229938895,4.5,-25.7748468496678));
#863=CARTESIAN_POINT('',(-0.927994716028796,4.5,-25.7422360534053));
#864=CARTESIAN_POINT('',(-0.704765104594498,4.5,-25.6926144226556));
#865=CARTESIAN_POINT('',(-0.602309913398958,4.5,-25.6739180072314));
#866=CARTESIAN_POINT('',(-0.396192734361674,4.5,-25.6451371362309));
#867=CARTESIAN_POINT('',(-0.292530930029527,4.5,-25.6350513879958));
#868=CARTESIAN_POINT('',(-0.0849035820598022,4.5,-25.6240115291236));
#869=CARTESIAN_POINT('',(0.0190610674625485,4.5,-25.6230408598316));
#870=CARTESIAN_POINT('',(0.226677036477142,4.5,-25.6302356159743));
#871=CARTESIAN_POINT('',(0.330328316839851,4.5,-25.6384021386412));
#872=CARTESIAN_POINT('',(0.558826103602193,4.5,-25.6661714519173));
#873=CARTESIAN_POINT('',(0.683419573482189,4.5,-25.687861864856));
#874=CARTESIAN_POINT('',(0.930070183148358,4.5,-25.7427051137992));
#875=CARTESIAN_POINT('',(1.05212589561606,4.5,-25.7758642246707));
#876=CARTESIAN_POINT('',(1.29373096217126,4.5,-25.8519835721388));
#877=CARTESIAN_POINT('',(1.41326576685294,4.5,-25.8949893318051));
#878=CARTESIAN_POINT('',(1.64912618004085,4.5,-25.9888630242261));
#879=CARTESIAN_POINT('',(1.76545261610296,4.5,-26.0397289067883));
#880=CARTESIAN_POINT('',(2.08022955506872,4.5,-26.1876658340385));
#881=CARTESIAN_POINT('',(2.27569357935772,4.5,-26.291055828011));
#882=CARTESIAN_POINT('',(2.65965824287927,4.5,-26.510129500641));
#883=CARTESIAN_POINT('',(2.84815185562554,4.5,-26.6258251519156));
#884=CARTESIAN_POINT('',(3.2206264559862,4.5,-26.865464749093));
#885=CARTESIAN_POINT('',(3.40459103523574,4.5,-26.9894339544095));
#886=CARTESIAN_POINT('',(3.76897708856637,4.5,-27.2422768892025));
#887=CARTESIAN_POINT('',(3.94939990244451,4.5,-27.3711487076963));
#888=CARTESIAN_POINT('',(4.30959038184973,4.5,-27.6329175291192));
#889=CARTESIAN_POINT('',(4.48934008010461,4.5,-27.7658391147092));
#890=CARTESIAN_POINT('',(4.84769993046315,4.5,-28.0332268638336));
#891=CARTESIAN_POINT('',(5.02631000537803,4.5,-28.1676931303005));
#892=CARTESIAN_POINT('',(5.38285547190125,4.5,-28.4368710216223));
#893=CARTESIAN_POINT('',(5.56079149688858,4.5,-28.5715818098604));
#894=CARTESIAN_POINT('',(5.91689994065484,4.5,-28.8406969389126));
#895=CARTESIAN_POINT('',(6.09507236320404,4.5,-28.9751012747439));
#896=CARTESIAN_POINT('',(6.51845290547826,4.5,-29.2927601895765));
#897=CARTESIAN_POINT('',(6.76396770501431,4.5,-29.4756076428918));
#898=CARTESIAN_POINT('',(7.25717026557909,4.5,-29.8383539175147));
#899=CARTESIAN_POINT('',(7.50485801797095,4.5,-30.0182527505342));
#900=CARTESIAN_POINT('',(8.00299141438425,4.5,-30.374186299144));
#901=CARTESIAN_POINT('',(8.25343697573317,4.5,-30.550221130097));
#902=CARTESIAN_POINT('',(8.75748514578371,4.5,-30.8977104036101));
#903=CARTESIAN_POINT('',(9.01108777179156,4.5,-31.0691648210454));
#904=CARTESIAN_POINT('',(9.77721510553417,4.5,-31.5758563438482));
#905=CARTESIAN_POINT('',(10.2949280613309,4.5,-31.9033270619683));
#906=CARTESIAN_POINT('',(11.3450798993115,4.5,-32.5338451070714));
#907=CARTESIAN_POINT('',(11.877519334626,4.5,-32.8368915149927));
#908=CARTESIAN_POINT('',(12.9541574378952,4.5,-33.4143106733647));
#909=CARTESIAN_POINT('',(13.4982794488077,4.5,-33.6888259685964));
#910=CARTESIAN_POINT('',(14.6002432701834,4.5,-34.2088544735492));
#911=CARTESIAN_POINT('',(15.1580853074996,4.5,-34.454367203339));
#912=CARTESIAN_POINT('',(16.286390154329,4.5,-34.9146730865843));
#913=CARTESIAN_POINT('',(16.8568541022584,4.5,-35.1294634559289));
#914=CARTESIAN_POINT('',(18.0088078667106,4.5,-35.5268449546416));
#915=CARTESIAN_POINT('',(18.5902966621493,4.5,-35.7094390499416));
#916=CARTESIAN_POINT('',(20.0165260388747,4.5,-36.1130976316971));
#917=CARTESIAN_POINT('',(20.8663068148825,4.5,-36.3166227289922));
#918=CARTESIAN_POINT('',(22.5794989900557,4.5,-36.652424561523));
#919=CARTESIAN_POINT('',(23.4429056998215,4.5,-36.7847252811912));
#920=CARTESIAN_POINT('',(25.1788937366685,4.5,-36.9764824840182));
#921=CARTESIAN_POINT('',(26.0514851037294,4.5,-37.0358485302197));
#922=CARTESIAN_POINT('',(27.7986551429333,4.5,-37.0803209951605));
#923=CARTESIAN_POINT('',(28.6732340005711,4.5,-37.0654201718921));
#924=CARTESIAN_POINT('',(30.4186265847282,4.5,-36.9608997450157));
#925=CARTESIAN_POINT('',(31.289436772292,4.5,-36.8712208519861));
#926=CARTESIAN_POINT('',(33.0201174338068,4.5,-36.6173414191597));
#927=CARTESIAN_POINT('',(33.8799881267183,4.5,-36.4531423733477));
#928=CARTESIAN_POINT('',(35.5821003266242,4.5,-36.0512093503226));
#929=CARTESIAN_POINT('',(36.4243470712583,4.5,-35.8134975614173));
#930=CARTESIAN_POINT('',(38.0851095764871,4.5,-35.266073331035));
#931=CARTESIAN_POINT('',(38.9036256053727,4.5,-34.9563617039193));
#932=CARTESIAN_POINT('',(40.4925929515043,4.5,-34.274865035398));
#933=CARTESIAN_POINT('',(41.2637115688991,4.5,-33.904634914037));
#934=CARTESIAN_POINT('',(42.7716979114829,4.5,-33.0999949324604));
#935=CARTESIAN_POINT('',(43.5085661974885,4.5,-32.6655861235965));
#936=CARTESIAN_POINT('',(44.9426667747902,4.5,-31.7356321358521));
#937=CARTESIAN_POINT('',(45.6398987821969,4.5,-31.2400865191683));
#938=CARTESIAN_POINT('',(46.9896031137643,4.5,-30.1913841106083));
#939=CARTESIAN_POINT('',(47.6420755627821,4.5,-29.6382274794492));
#940=CARTESIAN_POINT('',(48.891363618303,4.5,-28.4839074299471));
#941=CARTESIAN_POINT('',(49.4886578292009,4.5,-27.8832618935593));
#942=CARTESIAN_POINT('',(50.6303244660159,4.5,-26.6336248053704));
#943=CARTESIAN_POINT('',(51.1746972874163,4.5,-25.9846336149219));
#944=CARTESIAN_POINT('',(52.2065665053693,4.5,-24.642944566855));
#945=CARTESIAN_POINT('',(52.6940648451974,4.5,-23.9502482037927));
#946=CARTESIAN_POINT('',(53.6086759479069,4.5,-22.5260740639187));
#947=CARTESIAN_POINT('',(54.0357887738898,4.5,-21.7945963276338));
#948=CARTESIAN_POINT('',(54.8249218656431,4.5,-20.3011453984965));
#949=CARTESIAN_POINT('',(55.1872000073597,4.5,-19.5393084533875));
#950=CARTESIAN_POINT('',(55.8461836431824,4.5,-17.9877847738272));
#951=CARTESIAN_POINT('',(56.1428893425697,4.5,-17.1980981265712));
#952=CARTESIAN_POINT('',(56.668591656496,4.5,-15.5965045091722));
#953=CARTESIAN_POINT('',(56.8975886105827,4.5,-14.7845976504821));
#954=CARTESIAN_POINT('',(57.2862265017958,4.5,-13.144350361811));
#955=CARTESIAN_POINT('',(57.4458674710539,4.5,-12.3160099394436));
#956=CARTESIAN_POINT('',(57.6944225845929,4.5,-10.6502902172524));
#957=CARTESIAN_POINT('',(57.783461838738,4.5,-9.81292958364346));
#958=CARTESIAN_POINT('',(57.8906458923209,4.5,-8.13368390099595));
#959=CARTESIAN_POINT('',(57.9087907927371,4.5,-7.29179885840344));
#960=CARTESIAN_POINT('',(57.8740561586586,4.5,-5.60950140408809));
#961=CARTESIAN_POINT('',(57.8211771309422,4.5,-4.76908898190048));
#962=CARTESIAN_POINT('',(57.6447751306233,4.5,-3.09571117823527));
#963=CARTESIAN_POINT('',(57.5212521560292,4.5,-2.26274579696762));
#964=CARTESIAN_POINT('',(57.2045280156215,4.5,-0.610600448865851));
#965=CARTESIAN_POINT('',(57.0113616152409,4.5,0.208586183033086));
#966=CARTESIAN_POINT('',(56.5567261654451,4.5,1.82778068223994));
#967=CARTESIAN_POINT('',(56.2952571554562,4.5,2.6277885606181));
#968=CARTESIAN_POINT('',(55.7058883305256,4.5,4.2029541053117));
#969=CARTESIAN_POINT('',(55.3779880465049,4.5,4.97811159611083));
#970=CARTESIAN_POINT('',(54.6581068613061,4.5,6.49807652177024));
#971=CARTESIAN_POINT('',(54.2661259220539,4.5,7.24288393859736));
#972=CARTESIAN_POINT('',(53.4206580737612,4.5,8.69727722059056));
#973=CARTESIAN_POINT('',(52.9671375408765,4.5,9.40684353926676));
#974=CARTESIAN_POINT('',(52.002004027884,4.5,10.7853008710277));
#975=CARTESIAN_POINT('',(51.490391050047,4.5,11.4541918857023));
#976=CARTESIAN_POINT('',(50.4127466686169,4.5,12.7465698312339));
#977=CARTESIAN_POINT('',(49.8467165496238,4.5,13.3700578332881));
#978=CARTESIAN_POINT('',(48.6642736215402,4.5,14.5672713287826));
#979=CARTESIAN_POINT('',(48.0478607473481,4.5,15.1409967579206));
#980=CARTESIAN_POINT('',(46.7678900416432,4.5,16.2356730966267));
#981=CARTESIAN_POINT('',(46.1042486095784,4.5,16.7565262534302));
#982=CARTESIAN_POINT('',(44.7355620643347,4.5,17.7406453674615));
#983=CARTESIAN_POINT('',(44.0305169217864,4.5,18.2039112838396));
#984=CARTESIAN_POINT('',(42.5840120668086,4.5,19.0696922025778));
#985=CARTESIAN_POINT('',(41.8425502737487,4.5,19.47220372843));
#986=CARTESIAN_POINT('',(40.3285253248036,4.5,20.2137163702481));
#987=CARTESIAN_POINT('',(39.5559621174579,4.5,20.5527173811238));
#988=CARTESIAN_POINT('',(37.9819561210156,4.5,21.1662345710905));
#989=CARTESIAN_POINT('',(37.1804070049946,4.5,21.4404779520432));
#990=CARTESIAN_POINT('',(35.5571683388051,4.5,21.9209115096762));
#991=CARTESIAN_POINT('',(34.7354786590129,4.5,22.1271012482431));
#992=CARTESIAN_POINT('',(33.0778123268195,4.5,22.4701993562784));
#993=CARTESIAN_POINT('',(32.2418364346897,4.5,22.607111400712));
#994=CARTESIAN_POINT('',(30.5614263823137,4.5,22.8110090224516));
#995=CARTESIAN_POINT('',(29.7169923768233,4.5,22.8779958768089));
#996=CARTESIAN_POINT('',(28.0172278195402,4.5,22.9422784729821));
#997=CARTESIAN_POINT('',(27.1618713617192,4.5,22.93888757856));
#998=CARTESIAN_POINT('',(25.4543024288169,4.5,22.8612565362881));
#999=CARTESIAN_POINT('',(24.6020902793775,4.5,22.7870092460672));
#1000=CARTESIAN_POINT('',(22.9069326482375,4.5,22.5688941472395));
#1001=CARTESIAN_POINT('',(22.0639845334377,4.5,22.4250466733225));
#1002=CARTESIAN_POINT('',(20.3927216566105,4.5,22.0696369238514));
#1003=CARTESIAN_POINT('',(19.5644013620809,4.5,21.8581008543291));
#1004=CARTESIAN_POINT('',(18.4649117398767,4.5,21.5303249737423));
#1005=CARTESIAN_POINT('',(18.1849661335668,4.5,21.4426914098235));
#1006=CARTESIAN_POINT('',(17.6275945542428,4.5,21.2599103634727));
#1007=CARTESIAN_POINT('',(17.350168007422,4.5,21.1647646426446));
#1008=CARTESIAN_POINT('',(16.7988253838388,4.5,20.967395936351));
#1009=CARTESIAN_POINT('',(16.5249010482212,4.5,20.8651959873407));
#1010=CARTESIAN_POINT('',(15.9797711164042,4.5,20.6535867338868));
#1011=CARTESIAN_POINT('',(15.7085662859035,4.5,20.5441754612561));
#1012=CARTESIAN_POINT('',(15.4388208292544,4.5,20.4312501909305));
#1013=B_SPLINE_CURVE_WITH_KNOTS('',3,(#625,#626,#627,#628,#629,#630,#631,#632,#633,#634,#635,
#636,#637,#638,#639,#640,#641,#642,#643,#644,#645,#646,#647,#648,#649,#650,#651,#652,#653,#654,
#655,#656,#657,#658,#659,#660,#661,#662,#663,#664,#665,#666,#667,#668,#669,#670,#671,#672,#673,
#674,#675,#676,#677,#678,#679,#680,#681,#682,#683,#684,#685,#686,#687,#688,#689,#690,#691,#692,
#693,#694,#695,#696,#697,#698,#699,#700,#701,#702,#703,#704,#705,#706,#707,#708,#709,#710,#711,
#712,#713,#714,#715,#716,#717,#718,#719,#720,#721,#722,#723,#724,#725,#726,#727,#728,#729,#730,
#731,#732,#733,#734,#735,#736,#737,#738,#739,#740,#741,#742,#743,#744,#745,#746,#747,#748,#749,
#750,#751,#752,#753,#754,#755,#756,#757,#758,#759,#760,#761,#762,#763,#764,#765,#766,#767,#768,
#769,#770,#771,#772,#773,#774,#775,#776,#777,#778,#779,#780,#781,#782,#783,#784,#785,#786,#787,
#788,#789,#790,#791,#792,#793,#794,#795,#796,#797,#798,#799,#800,#801,#802,#803,#804,#805,#806,
#807,#808,#809,#810,#811,#812,#813,#814,#815,#816,#817,#818,#819,#820,#821,#822,#823,#824,#825,
#826,#827,#828,#829,#830,#831,#832,#833,#834,#835,#836,#837,#838,#839,#840,#841,#842,#843,#844,
#845,#846,#847,#848,#849,#850,#851,#852,#853,#854,#855,#856,#857,#858,#859,#860,#861,#862,#863,
#864,#865,#866,#867,#868,#869,#870,#871,#872,#873,#874,#875,#876,#877,#878,#879,#880,#881,#882,
#883,#884,#885,#886,#887,#888,#889,#890,#891,#892,#893,#894,#895,#896,#897,#898,#899,#900,#901,
#902,#903,#904,#905,#906,#907,#908,#909,#910,#911,#912,#913,#914,#915,#916,#917,#918,#919,#920,
#921,#922,#923,#924,#925,#926,#927,#928,#929,#930,#931,#932,#933,#934,#935,#936,#937,#938,#939,
#940,#941,#942,#943,#944,#945,#946,#947,#948,#949,#950,#951,#952,#953,#954,#955,#956,#957,#958,
#959,#960,#961,#962,#963,#964,#965,#966,#967,#968,#969,#970,#971,#972,#973,#974,#975,#976,#977,
#978,#979,#980,#981,#982,#983,#984,#985,#986,#987,#988,#989,#990,#991,#992,#993,#994,#995,#996,
#997,#998,#999,#1000,#1001,#1002,#1003,#1004,#1005,#1006,#1007,#1008,#1009,#1010,#1011,#1012),
.UNSPECIFIED.,.T.,.F.,(4,2,2,2,2,2,2,2,2,2,2,2,2,2,2,2,2,2,2,2,2,2,2,2,2,2,2,2,2,2,2,2,2,2,2,2,
2,2,2,2,2,2,2,2,2,2,2,2,2,2,2,2,2,2,2,2,2,2,2,2,2,2,2,2,2,2,2,2,2,2,2,2,2,2,2,2,2,2,2,2,2,2,2,2,
2,2,2,2,2,2,2,2,2,2,2,2,2,2,2,2,2,2,2,2,2,2,2,2,2,2,2,2,2,2,2,2,2,2,2,2,2,2,2,2,2,2,2,2,2,2,2,2,
2,2,2,2,2,2,2,2,2,2,2,2,2,2,2,2,2,2,2,2,2,2,2,2,2,2,2,2,2,2,2,2,2,2,2,2,2,2,2,2,2,2,2,2,2,2,2,2,
2,2,2,2,2,2,2,2,2,2,2,2,2,4),(0.,1.62807164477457,3.25642999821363,4.88492937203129,
6.51334393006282,8.16176131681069,8.98601514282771,9.8102659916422,10.6342878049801,
11.4583187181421,12.2822976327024,13.1062483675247,13.5571771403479,14.0081172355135,
14.4597840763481,14.9114332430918,15.3569463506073,15.8025657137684,16.2468578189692,
16.6908810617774,17.0191601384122,17.3474685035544,17.6751238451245,18.0027527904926,
18.3313376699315,18.659945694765,18.9892459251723,19.318556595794,20.0734469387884,
20.4518416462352,20.8301833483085,21.2124127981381,21.594651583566,21.9765333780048,
22.3584022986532,22.7967886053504,23.2351822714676,24.1120304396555,24.9890355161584,
25.8660324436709,26.7430832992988,27.6201405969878,28.4971384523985,29.3741436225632,
31.1080606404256,32.8420380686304,34.5769793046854,36.3119812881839,38.9677083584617,
41.6222994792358,44.2943134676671,46.9667394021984,49.6387234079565,52.3105995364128,
54.976506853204,57.642375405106,60.2197265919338,62.7970126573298,65.3757681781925,
67.9545168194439,70.4984377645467,73.0423308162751,75.58571307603,78.1290924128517,
80.6592156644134,83.1893287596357,85.7195218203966,88.249713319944,90.7739679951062,
93.2982180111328,95.8224308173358,98.3466433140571,100.868728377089,103.390811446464,
105.912899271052,108.434988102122,110.95762162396,113.480254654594,116.002857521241,
118.525463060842,121.051463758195,123.577465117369,126.10359783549,128.629736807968,
131.164213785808,133.698691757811,136.232674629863,138.766670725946,141.318509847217,
143.870345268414,145.147359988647,146.424302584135,147.70115723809,148.97829073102,
151.581248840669,154.184375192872,155.483418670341,156.782141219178,158.080948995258,
159.379820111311,160.493936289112,161.60806401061,162.721945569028,163.835834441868,
164.952323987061,166.068850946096,167.18536715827,167.743618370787,168.301869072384,
168.689510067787,169.077153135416,169.852689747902,170.239874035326,170.627032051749,
171.013967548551,171.40084910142,171.775354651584,172.149891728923,172.523811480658,
172.897545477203,173.209658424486,173.521724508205,173.833223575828,174.144760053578,
174.523525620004,174.902498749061,175.283260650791,175.663923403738,176.326521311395,
176.989769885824,177.655145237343,178.320263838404,178.99092115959,179.661623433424,
180.331156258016,181.000699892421,181.919051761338,182.837399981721,183.755720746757,
184.674046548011,186.51118318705,188.348388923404,190.175923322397,192.003487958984,
193.831218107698,195.658779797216,198.277105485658,200.894548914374,203.515234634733,
206.136175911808,208.75919723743,211.382165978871,214.004343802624,216.626491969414,
219.189590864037,221.752647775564,224.315723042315,226.878791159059,229.416990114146,
231.955170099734,234.493263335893,237.031353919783,239.559113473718,242.086865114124,
244.614604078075,247.142341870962,249.665590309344,252.188835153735,254.712061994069,
257.235288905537,259.757257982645,262.279225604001,264.80121103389,267.323197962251,
269.846568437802,272.369938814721,274.893249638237,277.416563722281,279.944461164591,
282.472360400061,285.000404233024,287.528452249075,290.066967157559,292.60549840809,
295.143894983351,297.682245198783,300.245372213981,302.808757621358,305.371394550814,
307.933040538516,308.812996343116,309.692746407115,310.56974830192,311.446990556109),.UNSPECIFIED.);
#1014=EDGE_CURVE('E261',#622,#519,#1013,.T.);
#1015=ORIENTED_EDGE('',*,*,#1014,.T.);
#1016=ORIENTED_EDGE('',*,*,#520,.T.);
#1017=ORIENTED_EDGE('',*,*,#415,.T.);
#1018=ORIENTED_EDGE('',*,*,#191,.F.);
#1019=ORIENTED_EDGE('',*,*,#359,.F.);
#1020=DIRECTION('',(0.707106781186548,0.,-0.707106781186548));
#1021=VECTOR('',#1020,1.);
#1022=CARTESIAN_POINT('',(27.1888202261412,4.5,18.3111797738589));
#1023=LINE('',#1022,#1021);
#1024=EDGE_CURVE('E449',#589,#352,#1023,.T.);
#1025=ORIENTED_EDGE('',*,*,#1024,.F.);
#1026=EDGE_LOOP('',(#591,#624,#1015,#1016,#1017,#1018,#1019,#1025));
#1027=FACE_BOUND('',#1026,.T.);
#1028=ADVANCED_FACE('F166',(#1027),#580,.F.);
#1029=CARTESIAN_POINT('',(25.5,-4.5,0.));
#1030=DIRECTION('',(0.,1.,0.));
#1031=DIRECTION('',(-1.,0.,0.));
#1032=AXIS2_PLACEMENT_3D('',#1029,#1030,#1031);
#1033=PLANE('',#1032);
#1034=CARTESIAN_POINT('',(15.4388208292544,-4.5,20.4312501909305));
#1035=CARTESIAN_POINT('',(15.8561117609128,-4.5,20.6059409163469));
#1036=CARTESIAN_POINT('',(16.2769268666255,-4.5,20.7722358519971));
#1037=CARTESIAN_POINT('',(17.1250355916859,-4.5,21.087419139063));
#1038=CARTESIAN_POINT('',(17.5523297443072,-4.5,21.236306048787));
#1039=CARTESIAN_POINT('',(18.8429460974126,-4.5,21.6559972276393));
#1040=CARTESIAN_POINT('',(19.7152063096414,-4.5,21.8999177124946));
#1041=CARTESIAN_POINT('',(21.4781682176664,-4.5,22.3126126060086));
#1042=CARTESIAN_POINT('',(22.3688874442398,-4.5,22.4813117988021));
#1043=CARTESIAN_POINT('',(24.1616685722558,-4.5,22.7408279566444));
#1044=CARTESIAN_POINT('',(25.0637305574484,-4.5,22.8316443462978));
#1045=CARTESIAN_POINT('',(26.86675363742,-4.5,22.9335126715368));
#1046=CARTESIAN_POINT('',(27.7676869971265,-4.5,22.945054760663));
#1047=CARTESIAN_POINT('',(29.5671078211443,-4.5,22.8889694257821));
#1048=CARTESIAN_POINT('',(30.465595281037,-4.5,22.8213418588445));
#1049=CARTESIAN_POINT('',(32.2530264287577,-4.5,22.6069888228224));
#1050=CARTESIAN_POINT('',(33.1419708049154,-4.5,22.4602690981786));
#1051=CARTESIAN_POINT('',(34.9033276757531,-4.5,22.088539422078));
#1052=CARTESIAN_POINT('',(35.7757407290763,-4.5,21.8635321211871));
#1053=CARTESIAN_POINT('',(37.4586142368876,-4.5,21.3485228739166));
#1054=CARTESIAN_POINT('',(38.2701017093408,-4.5,21.0618710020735));
#1055=CARTESIAN_POINT('',(39.8656672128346,-4.5,20.4204192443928));
#1056=CARTESIAN_POINT('',(40.6497461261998,-4.5,20.0656215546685));
#1057=CARTESIAN_POINT('',(42.1845826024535,-4.5,19.290397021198));
#1058=CARTESIAN_POINT('',(42.9353461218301,-4.5,18.8699819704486));
#1059=CARTESIAN_POINT('',(44.3981481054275,-4.5,17.9664459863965));
#1060=CARTESIAN_POINT('',(45.1101866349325,-4.5,17.4833251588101));
#1061=CARTESIAN_POINT('',(46.4809898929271,-4.5,16.4647276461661));
#1062=CARTESIAN_POINT('',(47.1403408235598,-4.5,15.9300396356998));
#1063=CARTESIAN_POINT('',(48.4114215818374,-4.5,14.8067814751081));
#1064=CARTESIAN_POINT('',(49.0231519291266,-4.5,14.2182119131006));
#1065=CARTESIAN_POINT('',(50.1945633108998,-4.5,12.9913621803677));
#1066=CARTESIAN_POINT('',(50.7542437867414,-4.5,12.3530814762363));
#1067=CARTESIAN_POINT('',(51.8174825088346,-4.5,11.0313705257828));
#1068=CARTESIAN_POINT('',(52.3210408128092,-4.5,10.3479403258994));
#1069=CARTESIAN_POINT('',(53.2658616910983,-4.5,8.94455830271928));
#1070=CARTESIAN_POINT('',(53.7074400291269,-4.5,8.22481904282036));
#1071=CARTESIAN_POINT('',(54.5282621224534,-4.5,6.75063433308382));
#1072=CARTESIAN_POINT('',(54.9075061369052,-4.5,5.99618902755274));
#1073=CARTESIAN_POINT('',(55.60091969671,-4.5,4.45798300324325));
#1074=CARTESIAN_POINT('',(55.9150906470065,-4.5,3.67422291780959));
#1075=CARTESIAN_POINT('',(56.476102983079,-4.5,2.08296442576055));
#1076=CARTESIAN_POINT('',(56.7229444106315,-4.5,1.2754660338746));
#1077=CARTESIAN_POINT('',(57.1470226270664,-4.5,-0.355597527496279));
#1078=CARTESIAN_POINT('',(57.3244200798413,-4.5,-1.17912092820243));
#1079=CARTESIAN_POINT('',(57.6091522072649,-4.5,-2.83819127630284));
#1080=CARTESIAN_POINT('',(57.7164870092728,-4.5,-3.67373820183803));
#1081=CARTESIAN_POINT('',(57.8603228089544,-4.5,-5.35090423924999));
#1082=CARTESIAN_POINT('',(57.8968240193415,-4.5,-6.1925233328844));
#1083=CARTESIAN_POINT('',(57.8987310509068,-4.5,-7.87584219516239));
#1084=CARTESIAN_POINT('',(57.8641368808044,-4.5,-8.71754196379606));
#1085=CARTESIAN_POINT('',(57.7241612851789,-4.5,-10.3943146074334));
#1086=CARTESIAN_POINT('',(57.6188399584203,-4.5,-11.2293925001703));
#1087=CARTESIAN_POINT('',(57.3382263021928,-4.5,-12.8877073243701));
#1088=CARTESIAN_POINT('',(57.1629340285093,-4.5,-13.7109442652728));
#1089=CARTESIAN_POINT('',(56.7436354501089,-4.5,-15.3397284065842));
#1090=CARTESIAN_POINT('',(56.4996291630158,-4.5,-16.14527561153));
#1091=CARTESIAN_POINT('',(55.9446516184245,-4.5,-17.7329621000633));
#1092=CARTESIAN_POINT('',(55.6336803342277,-4.5,-18.5151013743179));
#1093=CARTESIAN_POINT('',(54.946926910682,-4.5,-20.0505914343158));
#1094=CARTESIAN_POINT('',(54.5711307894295,-4.5,-20.8039359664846));
#1095=CARTESIAN_POINT('',(53.7574666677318,-4.5,-22.2763218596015));
#1096=CARTESIAN_POINT('',(53.3195986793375,-4.5,-22.9953632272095));
#1097=CARTESIAN_POINT('',(52.3849314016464,-4.5,-24.3940524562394));
#1098=CARTESIAN_POINT('',(51.8881327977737,-4.5,-25.0737007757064));
#1099=CARTESIAN_POINT('',(50.8391541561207,-4.5,-26.388822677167));
#1100=CARTESIAN_POINT('',(50.2869740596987,-4.5,-27.0242962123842));
#1101=CARTESIAN_POINT('',(49.1304008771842,-4.5,-28.2474275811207));
#1102=CARTESIAN_POINT('',(48.5259385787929,-4.5,-28.8350199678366));
#1103=CARTESIAN_POINT('',(47.2697662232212,-4.5,-29.9573178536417));
#1104=CARTESIAN_POINT('',(46.6180561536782,-4.5,-30.4920233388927));
#1105=CARTESIAN_POINT('',(45.272009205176,-4.5,-31.5048523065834));
#1106=CARTESIAN_POINT('',(44.5776701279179,-4.5,-31.9829728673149));
#1107=CARTESIAN_POINT('',(43.1513452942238,-4.5,-32.8793042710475));
#1108=CARTESIAN_POINT('',(42.4193594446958,-4.5,-33.2975149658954));
#1109=CARTESIAN_POINT('',(40.920476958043,-4.5,-34.0724589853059));
#1110=CARTESIAN_POINT('',(40.1534731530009,-4.5,-34.4289850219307));
#1111=CARTESIAN_POINT('',(38.5922807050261,-4.5,-35.0764796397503));
#1112=CARTESIAN_POINT('',(37.798092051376,-4.5,-35.367448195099));
#1113=CARTESIAN_POINT('',(36.1883263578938,-4.5,-35.8818982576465));
#1114=CARTESIAN_POINT('',(35.3727534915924,-4.5,-36.1053928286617));
#1115=CARTESIAN_POINT('',(33.7258125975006,-4.5,-36.4836202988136));
#1116=CARTESIAN_POINT('',(32.8944444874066,-4.5,-36.638352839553));
#1117=CARTESIAN_POINT('',(31.2158772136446,-4.5,-36.8790999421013));
#1118=CARTESIAN_POINT('',(30.3686078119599,-4.5,-36.9646232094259));
#1119=CARTESIAN_POINT('',(28.6697949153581,-4.5,-37.0648751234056));
#1120=CARTESIAN_POINT('',(27.818251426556,-4.5,-37.0796038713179));
#1121=CARTESIAN_POINT('',(26.5421645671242,-4.5,-37.0489022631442));
#1122=CARTESIAN_POINT('',(26.1168258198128,-4.5,-37.0298498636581));
#1123=CARTESIAN_POINT('',(25.2672926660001,-4.5,-36.9742388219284));
#1124=CARTESIAN_POINT('',(24.8430981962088,-4.5,-36.9376811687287));
#1125=CARTESIAN_POINT('',(23.9965967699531,-4.5,-36.8472038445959));
#1126=CARTESIAN_POINT('',(23.5742896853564,-4.5,-36.7932853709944));
#1127=CARTESIAN_POINT('',(22.7321559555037,-4.5,-36.6682709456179));
#1128=CARTESIAN_POINT('',(22.3123298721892,-4.5,-36.5971712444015));
#1129=CARTESIAN_POINT('',(21.0416320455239,-4.5,-36.3553778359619));
#1130=CARTESIAN_POINT('',(20.195708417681,-4.5,-36.1579152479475));
#1131=CARTESIAN_POINT('',(18.5226659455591,-4.5,-35.6950336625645));
#1132=CARTESIAN_POINT('',(17.6955483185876,-4.5,-35.4296102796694));
#1133=CARTESIAN_POINT('',(16.4735693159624,-4.5,-34.9835410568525));
#1134=CARTESIAN_POINT('',(16.0697387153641,-4.5,-34.8270358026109));
#1135=CARTESIAN_POINT('',(15.2685100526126,-4.5,-34.4985621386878));
#1136=CARTESIAN_POINT('',(14.8711104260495,-4.5,-34.3265975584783));
#1137=CARTESIAN_POINT('',(14.0830747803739,-4.5,-33.9677768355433));
#1138=CARTESIAN_POINT('',(13.6924392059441,-4.5,-33.7809197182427));
#1139=CARTESIAN_POINT('',(12.9182576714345,-4.5,-33.3930142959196));
#1140=CARTESIAN_POINT('',(12.5347120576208,-4.5,-33.1919653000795));
#1141=CARTESIAN_POINT('',(11.8291261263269,-4.5,-32.8061426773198));
#1142=CARTESIAN_POINT('',(11.506115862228,-4.5,-32.6231376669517));
#1143=CARTESIAN_POINT('',(10.8654914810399,-4.5,-32.2479132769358));
#1144=CARTESIAN_POINT('',(10.5478774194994,-4.5,-32.0556938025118));
#1145=CARTESIAN_POINT('',(9.91802916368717,-4.5,-31.6627998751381));
#1146=CARTESIAN_POINT('',(9.60579379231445,-4.5,-31.4621273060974));
#1147=CARTESIAN_POINT('',(8.98637291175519,-4.5,-31.0531438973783));
#1148=CARTESIAN_POINT('',(8.67918743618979,-4.5,-30.8448330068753));
#1149=CARTESIAN_POINT('',(8.06869277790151,-4.5,-30.4211518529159));
#1150=CARTESIAN_POINT('',(7.76539408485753,-4.5,-30.2057665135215));
#1151=CARTESIAN_POINT('',(7.16257759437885,-4.5,-29.769765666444));
#1152=CARTESIAN_POINT('',(6.86305992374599,-4.5,-29.5491499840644));
#1153=CARTESIAN_POINT('',(6.26655458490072,-4.5,-29.104545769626));
#1154=CARTESIAN_POINT('',(5.969566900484,-4.5,-28.8805572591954));
#1155=CARTESIAN_POINT('',(5.52446235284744,-4.5,-28.5440840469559));
#1156=CARTESIAN_POINT('',(5.37615787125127,-4.5,-28.4318452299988));
#1157=CARTESIAN_POINT('',(5.07931179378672,-4.5,-28.207680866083));
#1158=CARTESIAN_POINT('',(4.93077019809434,-4.5,-28.0957553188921));
#1159=CARTESIAN_POINT('',(4.67855918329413,-4.5,-27.9069047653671));
#1160=CARTESIAN_POINT('',(4.57506434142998,-4.5,-27.8297473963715));
#1161=CARTESIAN_POINT('',(4.3675683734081,-4.5,-27.6761177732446));
#1162=CARTESIAN_POINT('',(4.26356724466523,-4.5,-27.5996455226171));
#1163=CARTESIAN_POINT('',(3.95043632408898,-4.5,-27.3716155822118));
#1164=CARTESIAN_POINT('',(3.74024377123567,-4.5,-27.2214937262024));
#1165=CARTESIAN_POINT('',(3.42143125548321,-4.5,-27.0017423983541));
#1166=CARTESIAN_POINT('',(3.31465242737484,-4.5,-26.9294480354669));
#1167=CARTESIAN_POINT('',(3.09954264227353,-4.5,-26.7872121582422));
#1168=CARTESIAN_POINT('',(2.99121178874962,-4.5,-26.7172704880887));
#1169=CARTESIAN_POINT('',(2.77269271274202,-4.5,-26.5804757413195));
#1170=CARTESIAN_POINT('',(2.66250556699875,-4.5,-26.5136209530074));
#1171=CARTESIAN_POINT('',(2.43983349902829,-4.5,-26.3838630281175));
#1172=CARTESIAN_POINT('',(2.32734889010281,-4.5,-26.3209593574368));
#1173=CARTESIAN_POINT('',(2.1029232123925,-4.5,-26.2019540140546));
#1174=CARTESIAN_POINT('',(1.99105856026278,-4.5,-26.1457092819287));
#1175=CARTESIAN_POINT('',(1.76443399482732,-4.5,-26.0392996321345));
#1176=CARTESIAN_POINT('',(1.64967383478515,-4.5,-25.9891352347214));
#1177=CARTESIAN_POINT('',(1.41726304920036,-4.5,-25.8965271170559));
#1178=CARTESIAN_POINT('',(1.29961747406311,-4.5,-25.8540708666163));
#1179=CARTESIAN_POINT('',(1.06135919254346,-4.5,-25.7785557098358));
#1180=CARTESIAN_POINT('',(0.940747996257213,-4.5,-25.7454921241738));
#1181=CARTESIAN_POINT('',(0.717325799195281,-4.5,-25.695093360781));
#1182=CARTESIAN_POINT('',(0.614901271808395,-4.5,-25.6760546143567));
#1183=CARTESIAN_POINT('',(0.40881703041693,-4.5,-25.6465654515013));
#1184=CARTESIAN_POINT('',(0.305157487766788,-4.5,-25.6361138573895));
#1185=CARTESIAN_POINT('',(0.0974730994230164,-4.5,-25.6243341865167));
#1186=CARTESIAN_POINT('',(-0.0065509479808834,-4.5,-25.6229922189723));
#1187=CARTESIAN_POINT('',(-0.214314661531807,-4.5,-25.6294656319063));
#1188=CARTESIAN_POINT('',(-0.318054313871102,-4.5,-25.6372814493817));
#1189=CARTESIAN_POINT('',(-0.524007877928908,-4.5,-25.6616120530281));
#1190=CARTESIAN_POINT('',(-0.626226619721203,-4.5,-25.6780865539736));
#1191=CARTESIAN_POINT('',(-0.829059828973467,-4.5,-25.7189487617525));
#1192=CARTESIAN_POINT('',(-0.929674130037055,-4.5,-25.7433372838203));
#1193=CARTESIAN_POINT('',(-1.12915582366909,-4.5,-25.7991183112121));
#1194=CARTESIAN_POINT('',(-1.22801896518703,-4.5,-25.8305258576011));
#1195=CARTESIAN_POINT('',(-1.42359250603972,-4.5,-25.8992802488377));
#1196=CARTESIAN_POINT('',(-1.5203036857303,-4.5,-25.9366248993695));
#1197=CARTESIAN_POINT('',(-1.83088552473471,-4.5,-26.0659040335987));
#1198=CARTESIAN_POINT('',(-2.04057438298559,-4.5,-26.1678740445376));
#1199=CARTESIAN_POINT('',(-2.45140510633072,-4.5,-26.3879372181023));
#1200=CARTESIAN_POINT('',(-2.65253263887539,-4.5,-26.5060561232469));
#1201=CARTESIAN_POINT('',(-3.04941801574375,-4.5,-26.7530211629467));
#1202=CARTESIAN_POINT('',(-3.24514386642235,-4.5,-26.8819181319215));
#1203=CARTESIAN_POINT('',(-3.63213393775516,-4.5,-27.1459110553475));
#1204=CARTESIAN_POINT('',(-3.82340085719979,-4.5,-27.2810031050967));
#1205=CARTESIAN_POINT('',(-4.20606755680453,-4.5,-27.556898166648));
#1206=CARTESIAN_POINT('',(-4.39742748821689,-4.5,-27.6977560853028));
#1207=CARTESIAN_POINT('',(-4.77871648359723,-4.5,-27.9814300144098));
#1208=CARTESIAN_POINT('',(-4.96864537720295,-4.5,-28.1242462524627));
#1209=CARTESIAN_POINT('',(-5.34749309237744,-4.5,-28.4101054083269));
#1210=CARTESIAN_POINT('',(-5.53641325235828,-4.5,-28.5531465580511));
#1211=CARTESIAN_POINT('',(-5.91450376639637,-4.5,-28.8388977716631));
#1212=CARTESIAN_POINT('',(-6.10367412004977,-4.5,-28.9816078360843));
#1213=CARTESIAN_POINT('',(-6.53425921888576,-4.5,-29.3045463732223));
#1214=CARTESIAN_POINT('',(-6.77592084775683,-4.5,-29.4844469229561));
#1215=CARTESIAN_POINT('',(-7.26135519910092,-4.5,-29.8413822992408));
#1216=CARTESIAN_POINT('',(-7.50512791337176,-4.5,-30.0184171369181));
#1217=CARTESIAN_POINT('',(-7.99534334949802,-4.5,-30.3687495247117));
#1218=CARTESIAN_POINT('',(-8.24178601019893,-4.5,-30.5420471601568));
#1219=CARTESIAN_POINT('',(-8.7377223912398,-4.5,-30.8842194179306));
#1220=CARTESIAN_POINT('',(-8.98721612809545,-4.5,-31.0530940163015));
#1221=CARTESIAN_POINT('',(-9.74101391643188,-4.5,-31.5524332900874));
#1222=CARTESIAN_POINT('',(-10.2503354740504,-4.5,-31.8753976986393));
#1223=CARTESIAN_POINT('',(-11.2832362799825,-4.5,-32.4977580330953));
#1224=CARTESIAN_POINT('',(-11.8068159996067,-4.5,-32.79715317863));
#1225=CARTESIAN_POINT('',(-12.8640779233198,-4.5,-33.3675513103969));
#1226=CARTESIAN_POINT('',(-13.3976519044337,-4.5,-33.6387543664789));
#1227=CARTESIAN_POINT('',(-14.4780934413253,-4.5,-34.1533127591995));
#1228=CARTESIAN_POINT('',(-15.0249611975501,-4.5,-34.39666767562));
#1229=CARTESIAN_POINT('',(-16.1309303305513,-4.5,-34.8538591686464));
#1230=CARTESIAN_POINT('',(-16.6900317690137,-4.5,-35.0676955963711));
#1231=CARTESIAN_POINT('',(-17.8190243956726,-4.5,-35.4644474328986));
#1232=CARTESIAN_POINT('',(-18.3889146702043,-4.5,-35.6473654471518));
#1233=CARTESIAN_POINT('',(-19.8024066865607,-4.5,-36.057952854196));
#1234=CARTESIAN_POINT('',(-20.6513504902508,-4.5,-36.2675140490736));
#1235=CARTESIAN_POINT('',(-22.3633995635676,-4.5,-36.6154834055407));
#1236=CARTESIAN_POINT('',(-23.2265005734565,-4.5,-36.7539125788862));
#1237=CARTESIAN_POINT('',(-24.9625737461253,-4.5,-36.9579723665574));
#1238=CARTESIAN_POINT('',(-25.8355583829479,-4.5,-37.0234973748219));
#1239=CARTESIAN_POINT('',(-27.5840274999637,-4.5,-37.0802106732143));
#1240=CARTESIAN_POINT('',(-28.4595121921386,-4.5,-37.0713924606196));
#1241=CARTESIAN_POINT('',(-30.2071469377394,-4.5,-36.9789130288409));
#1242=CARTESIAN_POINT('',(-31.0792942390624,-4.5,-36.8951996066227));
#1243=CARTESIAN_POINT('',(-32.8131528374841,-4.5,-36.6530782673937));
#1244=CARTESIAN_POINT('',(-33.6748643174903,-4.5,-36.4946716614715));
#1245=CARTESIAN_POINT('',(-35.3811752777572,-4.5,-36.1040918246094));
#1246=CARTESIAN_POINT('',(-36.2257791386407,-4.5,-35.871937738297));
#1247=CARTESIAN_POINT('',(-37.8917098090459,-4.5,-35.3353565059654));
#1248=CARTESIAN_POINT('',(-38.7130369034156,-4.5,-35.0309302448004));
#1249=CARTESIAN_POINT('',(-40.3075403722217,-4.5,-34.3597619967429));
#1250=CARTESIAN_POINT('',(-41.0813904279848,-4.5,-33.9946194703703));
#1251=CARTESIAN_POINT('',(-42.5952551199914,-4.5,-33.1998923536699));
#1252=CARTESIAN_POINT('',(-43.335270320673,-4.5,-32.7703088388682));
#1253=CARTESIAN_POINT('',(-44.776026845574,-4.5,-31.8497253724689));
#1254=CARTESIAN_POINT('',(-45.4767694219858,-4.5,-31.3587273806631));
#1255=CARTESIAN_POINT('',(-46.8338604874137,-4.5,-30.3187935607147));
#1256=CARTESIAN_POINT('',(-47.4902091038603,-4.5,-29.7698578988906));
#1257=CARTESIAN_POINT('',(-48.7474352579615,-4.5,-28.6236837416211));
#1258=CARTESIAN_POINT('',(-49.3487966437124,-4.5,-28.026975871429));
#1259=CARTESIAN_POINT('',(-50.4989132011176,-4.5,-26.784853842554));
#1260=CARTESIAN_POINT('',(-51.0476687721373,-4.5,-26.1394400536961));
#1261=CARTESIAN_POINT('',(-52.0885948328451,-4.5,-24.8045090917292));
#1262=CARTESIAN_POINT('',(-52.5807663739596,-4.5,-24.1149927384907));
#1263=CARTESIAN_POINT('',(-53.5049709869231,-4.5,-22.6967684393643));
#1264=CARTESIAN_POINT('',(-53.937004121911,-4.5,-21.9680605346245));
#1265=CARTESIAN_POINT('',(-54.7361398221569,-4.5,-20.4797620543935));
#1266=CARTESIAN_POINT('',(-55.1035038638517,-4.5,-19.7203118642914));
#1267=CARTESIAN_POINT('',(-55.772840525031,-4.5,-18.1731233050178));
#1268=CARTESIAN_POINT('',(-56.0748133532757,-4.5,-17.3853850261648));
#1269=CARTESIAN_POINT('',(-56.6111913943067,-4.5,-15.7872408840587));
#1270=CARTESIAN_POINT('',(-56.8455973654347,-4.5,-14.976835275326));
#1271=CARTESIAN_POINT('',(-57.2451582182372,-4.5,-13.3391280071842));
#1272=CARTESIAN_POINT('',(-57.4103131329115,-4.5,-12.5118263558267));
#1273=CARTESIAN_POINT('',(-57.669947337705,-4.5,-10.8477391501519));
#1274=CARTESIAN_POINT('',(-57.7645538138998,-4.5,-10.0109734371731));
#1275=CARTESIAN_POINT('',(-57.8829015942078,-4.5,-8.33244621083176));
#1276=CARTESIAN_POINT('',(-57.9066430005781,-4.5,-7.49068470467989));
#1277=CARTESIAN_POINT('',(-57.8830903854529,-4.5,-5.80815814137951));
#1278=CARTESIAN_POINT('',(-57.835796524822,-4.5,-4.96739308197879));
#1279=CARTESIAN_POINT('',(-57.6705131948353,-4.5,-3.29284080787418));
#1280=CARTESIAN_POINT('',(-57.552523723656,-4.5,-2.45905359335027));
#1281=CARTESIAN_POINT('',(-57.2467751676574,-4.5,-0.804816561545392));
#1282=CARTESIAN_POINT('',(-57.0590521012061,-4.5,0.0156399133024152));
#1283=CARTESIAN_POINT('',(-56.6151755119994,-4.5,1.6378275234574));
#1284=CARTESIAN_POINT('',(-56.3590220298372,-4.5,2.4395586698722));
#1285=CARTESIAN_POINT('',(-55.780122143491,-4.5,4.01860141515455));
#1286=CARTESIAN_POINT('',(-55.4573761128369,-4.5,4.79591315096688));
#1287=CARTESIAN_POINT('',(-54.7476024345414,-4.5,6.32061202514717));
#1288=CARTESIAN_POINT('',(-54.3605747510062,-4.5,7.06799914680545));
#1289=CARTESIAN_POINT('',(-53.5247939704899,-4.5,8.5279349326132));
#1290=CARTESIAN_POINT('',(-53.0760092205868,-4.5,9.24046547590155));
#1291=CARTESIAN_POINT('',(-52.1200808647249,-4.5,10.625239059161));
#1292=CARTESIAN_POINT('',(-51.6129372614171,-4.5,11.2974821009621));
#1293=CARTESIAN_POINT('',(-50.5439125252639,-4.5,12.5969523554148));
#1294=CARTESIAN_POINT('',(-49.9820305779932,-4.5,13.2241788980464));
#1295=CARTESIAN_POINT('',(-48.8075520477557,-4.5,14.4292015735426));
#1296=CARTESIAN_POINT('',(-48.1949553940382,-4.5,15.0069976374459));
#1297=CARTESIAN_POINT('',(-46.9222654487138,-4.5,16.1101243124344));
#1298=CARTESIAN_POINT('',(-46.2620879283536,-4.5,16.6353577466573));
#1299=CARTESIAN_POINT('',(-44.8999454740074,-4.5,17.6285071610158));
#1300=CARTESIAN_POINT('',(-44.1979805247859,-4.5,18.0964231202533));
#1301=CARTESIAN_POINT('',(-42.7573041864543,-4.5,18.9716949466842));
#1302=CARTESIAN_POINT('',(-42.01859441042,-4.5,19.3790534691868));
#1303=CARTESIAN_POINT('',(-40.5096556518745,-4.5,20.1304713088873));
#1304=CARTESIAN_POINT('',(-39.7394265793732,-4.5,20.474530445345));
#1305=CARTESIAN_POINT('',(-38.1697423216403,-4.5,21.0983266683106));
#1306=CARTESIAN_POINT('',(-37.3701815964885,-4.5,21.3777981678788));
#1307=CARTESIAN_POINT('',(-35.7504788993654,-4.5,21.8688327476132));
#1308=CARTESIAN_POINT('',(-34.9303369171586,-4.5,22.080395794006));
#1309=CARTESIAN_POINT('',(-33.2751770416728,-4.5,22.4343743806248));
#1310=CARTESIAN_POINT('',(-32.440157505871,-4.5,22.5767822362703));
#1311=CARTESIAN_POINT('',(-30.7611697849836,-4.5,22.7917102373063));
#1312=CARTESIAN_POINT('',(-29.9172015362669,-4.5,22.8642298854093));
#1313=CARTESIAN_POINT('',(-28.2181957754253,-4.5,22.9396124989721));
#1314=CARTESIAN_POINT('',(-27.3631290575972,-4.5,22.9418102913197));
#1315=CARTESIAN_POINT('',(-25.6556665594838,-4.5,22.8753237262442));
#1316=CARTESIAN_POINT('',(-24.8032707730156,-4.5,22.806639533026));
#1317=CARTESIAN_POINT('',(-23.5313930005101,-4.5,22.6513779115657));
#1318=CARTESIAN_POINT('',(-23.1085598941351,-4.5,22.5909195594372));
#1319=CARTESIAN_POINT('',(-22.2657073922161,-4.5,22.4528004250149));
#1320=CARTESIAN_POINT('',(-21.8456878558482,-4.5,22.375140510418));
#1321=CARTESIAN_POINT('',(-21.00917569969,-4.5,22.2028732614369));
#1322=CARTESIAN_POINT('',(-20.59268285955,-4.5,22.1082669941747));
#1323=CARTESIAN_POINT('',(-19.7637526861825,-4.5,21.9023821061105));
#1324=CARTESIAN_POINT('',(-19.3513161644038,-4.5,21.7911002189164));
#1325=CARTESIAN_POINT('',(-18.5204902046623,-4.5,21.5491075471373));
#1326=CARTESIAN_POINT('',(-18.1022264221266,-4.5,21.417965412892));
#1327=CARTESIAN_POINT('',(-17.2713184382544,-4.5,21.1389427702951));
#1328=CARTESIAN_POINT('',(-16.8586743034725,-4.5,20.9910620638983));
#1329=CARTESIAN_POINT('',(-16.0395222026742,-4.5,20.6790464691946));
#1330=CARTESIAN_POINT('',(-15.6330150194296,-4.5,20.5149095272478));
#1331=CARTESIAN_POINT('',(-14.8267225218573,-4.5,20.1709913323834));
#1332=CARTESIAN_POINT('',(-14.4269365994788,-4.5,19.9912115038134));
#1333=CARTESIAN_POINT('',(-13.6347045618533,-4.5,19.6167786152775));
#1334=CARTESIAN_POINT('',(-13.2422540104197,-4.5,19.4221349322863));
#1335=CARTESIAN_POINT('',(-12.464823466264,-4.5,19.018696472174));
#1336=CARTESIAN_POINT('',(-12.0798417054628,-4.5,18.8099050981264));
#1337=CARTESIAN_POINT('',(-11.3174013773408,-4.5,18.3790390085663));
#1338=CARTESIAN_POINT('',(-10.9399427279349,-4.5,18.1569644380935));
#1339=CARTESIAN_POINT('',(-10.1924778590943,-4.5,17.7006091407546));
#1340=CARTESIAN_POINT('',(-9.82247184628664,-4.5,17.4663280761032));
#1341=CARTESIAN_POINT('',(-9.08559987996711,-4.5,16.9843000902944));
#1342=CARTESIAN_POINT('',(-8.71881175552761,-4.5,16.7364344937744));
#1343=CARTESIAN_POINT('',(-7.99179201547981,-4.5,16.231395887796));
#1344=CARTESIAN_POINT('',(-7.63155957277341,-4.5,15.9742240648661));
#1345=CARTESIAN_POINT('',(-7.09481971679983,-4.5,15.5831540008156));
#1346=CARTESIAN_POINT('',(-6.91641530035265,-4.5,15.4518416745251));
#1347=CARTESIAN_POINT('',(-6.5605876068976,-4.5,15.1878936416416));
#1348=CARTESIAN_POINT('',(-6.38316433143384,-4.5,15.0552579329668));
#1349=CARTESIAN_POINT('',(-6.02896541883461,-4.5,14.7891582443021));
#1350=CARTESIAN_POINT('',(-5.85218972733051,-4.5,14.6556943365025));
#1351=CARTESIAN_POINT('',(-5.49880469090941,-4.5,14.3885487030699));
#1352=CARTESIAN_POINT('',(-5.32219534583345,-4.5,14.2548669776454));
#1353=CARTESIAN_POINT('',(-4.90867410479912,-4.5,13.9428793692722));
#1354=CARTESIAN_POINT('',(-4.67159483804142,-4.5,13.7647925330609));
#1355=CARTESIAN_POINT('',(-4.31385366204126,-4.5,13.5003918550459));
#1356=CARTESIAN_POINT('',(-4.19422078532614,-4.5,13.4126902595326));
#1357=CARTESIAN_POINT('',(-3.95393433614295,-4.5,13.238698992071));
#1358=CARTESIAN_POINT('',(-3.83328078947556,-4.5,13.1524092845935));
#1359=CARTESIAN_POINT('',(-3.59071246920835,-4.5,12.9819298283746));
#1360=CARTESIAN_POINT('',(-3.46879940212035,-4.5,12.8977376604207));
#1361=CARTESIAN_POINT('',(-3.22312011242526,-4.5,12.7321098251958));
#1362=CARTESIAN_POINT('',(-3.09935403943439,-4.5,12.6506739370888));
#1363=CARTESIAN_POINT('',(-2.84953374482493,-4.5,12.4916033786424));
#1364=CARTESIAN_POINT('',(-2.72348150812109,-4.5,12.4139656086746));
#1365=CARTESIAN_POINT('',(-2.4684216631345,-4.5,12.2637217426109));
#1366=CARTESIAN_POINT('',(-2.33941468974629,-4.5,12.1911145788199));
#1367=CARTESIAN_POINT('',(-2.09611955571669,-4.5,12.0623055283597));
#1368=CARTESIAN_POINT('',(-1.98229720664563,-4.5,12.0052296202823));
#1369=CARTESIAN_POINT('',(-1.75164322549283,-4.5,11.8974097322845));
#1370=CARTESIAN_POINT('',(-1.63481121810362,-4.5,11.8466665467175));
#1371=CARTESIAN_POINT('',(-1.39821969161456,-4.5,11.7532751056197));
#1372=CARTESIAN_POINT('',(-1.27846728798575,-4.5,11.7106090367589));
#1373=CARTESIAN_POINT('',(-1.03591448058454,-4.5,11.6351075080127));
#1374=CARTESIAN_POINT('',(-0.913115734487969,-4.5,11.6022668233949));
#1375=CARTESIAN_POINT('',(-0.687245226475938,-4.5,11.5530866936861));
#1376=CARTESIAN_POINT('',(-0.58459007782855,-4.5,11.5348432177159));
#1377=CARTESIAN_POINT('',(-0.378107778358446,-4.5,11.5070275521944));
#1378=CARTESIAN_POINT('',(-0.274280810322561,-4.5,11.4974540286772));
#1379=CARTESIAN_POINT('',(-0.0663499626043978,-4.5,11.4874736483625));
#1380=CARTESIAN_POINT('',(0.0377531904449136,-4.5,11.4870518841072));
#1381=CARTESIAN_POINT('',(0.245597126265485,-4.5,11.495355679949));
#1382=CARTESIAN_POINT('',(0.349337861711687,-4.5,11.5040823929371));
#1383=CARTESIAN_POINT('',(0.57874810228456,-4.5,11.5331714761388));
#1384=CARTESIAN_POINT('',(0.704144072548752,-4.5,11.5556961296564));
#1385=CARTESIAN_POINT('',(0.952319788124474,-4.5,11.6122767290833));
#1386=CARTESIAN_POINT('',(1.07509801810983,-4.5,11.6463391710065));
#1387=CARTESIAN_POINT('',(1.31811581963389,-4.5,11.7242962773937));
#1388=CARTESIAN_POINT('',(1.43833986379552,-4.5,11.7682386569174));
#1389=CARTESIAN_POINT('',(1.67553516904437,-4.5,11.8639761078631));
#1390=CARTESIAN_POINT('',(1.79250732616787,-4.5,11.9157689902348));
#1391=CARTESIAN_POINT('',(2.11305008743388,-4.5,12.0681209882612));
#1392=CARTESIAN_POINT('',(2.31343205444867,-4.5,12.1753505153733));
#1393=CARTESIAN_POINT('',(2.70700145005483,-4.5,12.4023734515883));
#1394=CARTESIAN_POINT('',(2.90018140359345,-4.5,12.5221794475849));
#1395=CARTESIAN_POINT('',(3.28196897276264,-4.5,12.7701259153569));
#1396=CARTESIAN_POINT('',(3.47055948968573,-4.5,12.8982924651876));
#1397=CARTESIAN_POINT('',(3.84419851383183,-4.5,13.1594802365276));
#1398=CARTESIAN_POINT('',(4.0292484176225,-4.5,13.2924994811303));
#1399=CARTESIAN_POINT('',(4.398547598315,-4.5,13.5623066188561));
#1400=CARTESIAN_POINT('',(4.58278233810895,-4.5,13.6991142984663));
#1401=CARTESIAN_POINT('',(4.95022227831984,-4.5,13.9741278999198));
#1402=CARTESIAN_POINT('',(5.13342739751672,-4.5,14.1123339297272));
#1403=CARTESIAN_POINT('',(5.49926330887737,-4.5,14.3887999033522));
#1404=CARTESIAN_POINT('',(5.68189453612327,-4.5,14.5270592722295));
#1405=CARTESIAN_POINT('',(6.04752641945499,-4.5,14.8030891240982));
#1406=CARTESIAN_POINT('',(6.23052707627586,-4.5,14.9408596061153));
#1407=CARTESIAN_POINT('',(6.76546252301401,-4.5,15.3410030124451));
#1408=CARTESIAN_POINT('',(7.11853334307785,-4.5,15.6018686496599));
#1409=CARTESIAN_POINT('',(7.83000188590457,-4.5,16.116261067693));
#1410=CARTESIAN_POINT('',(8.18839955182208,-4.5,16.3697879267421));
#1411=CARTESIAN_POINT('',(8.91193225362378,-4.5,16.867438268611));
#1412=CARTESIAN_POINT('',(9.27707034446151,-4.5,17.1115573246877));
#1413=CARTESIAN_POINT('',(10.0145830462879,-4.5,17.5886036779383));
#1414=CARTESIAN_POINT('',(10.3869573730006,-4.5,17.8215314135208));
#1415=CARTESIAN_POINT('',(11.1379806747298,-4.5,18.2741492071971));
#1416=CARTESIAN_POINT('',(11.5166044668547,-4.5,18.4938809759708));
#1417=CARTESIAN_POINT('',(12.2813511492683,-4.5,18.919899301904));
#1418=CARTESIAN_POINT('',(12.6674740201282,-4.5,19.1261858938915));
#1419=CARTESIAN_POINT('',(13.4470663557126,-4.5,19.52444544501));
#1420=CARTESIAN_POINT('',(13.8405361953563,-4.5,19.7164176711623));
#1421=CARTESIAN_POINT('',(14.6345106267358,-4.5,20.0852979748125));
#1422=CARTESIAN_POINT('',(15.0350156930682,-4.5,20.2622050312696));
#1423=CARTESIAN_POINT('',(15.4388208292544,-4.5,20.4312501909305));
#1424=B_SPLINE_CURVE_WITH_KNOTS('',3,(#1034,#1035,#1036,#1037,#1038,#1039,#1040,#1041,#1042,
#1043,#1044,#1045,#1046,#1047,#1048,#1049,#1050,#1051,#1052,#1053,#1054,#1055,#1056,#1057,#1058,
#1059,#1060,#1061,#1062,#1063,#1064,#1065,#1066,#1067,#1068,#1069,#1070,#1071,#1072,#1073,#1074,
#1075,#1076,#1077,#1078,#1079,#1080,#1081,#1082,#1083,#1084,#1085,#1086,#1087,#1088,#1089,#1090,
#1091,#1092,#1093,#1094,#1095,#1096,#1097,#1098,#1099,#1100,#1101,#1102,#1103,#1104,#1105,#1106,
#1107,#1108,#1109,#1110,#1111,#1112,#1113,#1114,#1115,#1116,#1117,#1118,#1119,#1120,#1121,#1122,
#1123,#1124,#1125,#1126,#1127,#1128,#1129,#1130,#1131,#1132,#1133,#1134,#1135,#1136,#1137,#1138,
#1139,#1140,#1141,#1142,#1143,#1144,#1145,#1146,#1147,#1148,#1149,#1150,#1151,#1152,#1153,#1154,
#1155,#1156,#1157,#1158,#1159,#1160,#1161,#1162,#1163,#1164,#1165,#1166,#1167,#1168,#1169,#1170,
#1171,#1172,#1173,#1174,#1175,#1176,#1177,#1178,#1179,#1180,#1181,#1182,#1183,#1184,#1185,#1186,
#1187,#1188,#1189,#1190,#1191,#1192,#1193,#1194,#1195,#1196,#1197,#1198,#1199,#1200,#1201,#1202,
#1203,#1204,#1205,#1206,#1207,#1208,#1209,#1210,#1211,#1212,#1213,#1214,#1215,#1216,#1217,#1218,
#1219,#1220,#1221,#1222,#1223,#1224,#1225,#1226,#1227,#1228,#1229,#1230,#1231,#1232,#1233,#1234,
#1235,#1236,#1237,#1238,#1239,#1240,#1241,#1242,#1243,#1244,#1245,#1246,#1247,#1248,#1249,#1250,
#1251,#1252,#1253,#1254,#1255,#1256,#1257,#1258,#1259,#1260,#1261,#1262,#1263,#1264,#1265,#1266,
#1267,#1268,#1269,#1270,#1271,#1272,#1273,#1274,#1275,#1276,#1277,#1278,#1279,#1280,#1281,#1282,
#1283,#1284,#1285,#1286,#1287,#1288,#1289,#1290,#1291,#1292,#1293,#1294,#1295,#1296,#1297,#1298,
#1299,#1300,#1301,#1302,#1303,#1304,#1305,#1306,#1307,#1308,#1309,#1310,#1311,#1312,#1313,#1314,
#1315,#1316,#1317,#1318,#1319,#1320,#1321,#1322,#1323,#1324,#1325,#1326,#1327,#1328,#1329,#1330,
#1331,#1332,#1333,#1334,#1335,#1336,#1337,#1338,#1339,#1340,#1341,#1342,#1343,#1344,#1345,#1346,
#1347,#1348,#1349,#1350,#1351,#1352,#1353,#1354,#1355,#1356,#1357,#1358,#1359,#1360,#1361,#1362,
#1363,#1364,#1365,#1366,#1367,#1368,#1369,#1370,#1371,#1372,#1373,#1374,#1375,#1376,#1377,#1378,
#1379,#1380,#1381,#1382,#1383,#1384,#1385,#1386,#1387,#1388,#1389,#1390,#1391,#1392,#1393,#1394,
#1395,#1396,#1397,#1398,#1399,#1400,#1401,#1402,#1403,#1404,#1405,#1406,#1407,#1408,#1409,#1410,
#1411,#1412,#1413,#1414,#1415,#1416,#1417,#1418,#1419,#1420,#1421,#1422,#1423),.UNSPECIFIED.,
.T.,.F.,(4,2,2,2,2,2,2,2,2,2,2,2,2,2,2,2,2,2,2,2,2,2,2,2,2,2,2,2,2,2,2,2,2,2,2,2,2,2,2,2,2,2,2,
2,2,2,2,2,2,2,2,2,2,2,2,2,2,2,2,2,2,2,2,2,2,2,2,2,2,2,2,2,2,2,2,2,2,2,2,2,2,2,2,2,2,2,2,2,2,2,2,
2,2,2,2,2,2,2,2,2,2,2,2,2,2,2,2,2,2,2,2,2,2,2,2,2,2,2,2,2,2,2,2,2,2,2,2,2,2,2,2,2,2,2,2,2,2,2,2,
2,2,2,2,2,2,2,2,2,2,2,2,2,2,2,2,2,2,2,2,2,2,2,2,2,2,2,2,2,2,2,2,2,2,2,2,2,2,2,2,2,2,2,2,2,2,2,2,
2,2,2,2,2,2,2,4),(0.,1.35704731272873,2.714206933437,5.42786400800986,8.14422849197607,
10.8606130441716,13.5601869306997,16.2597656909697,18.9591484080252,21.6584397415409,
24.2372240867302,26.8159253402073,29.3941636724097,31.9723976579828,34.5160692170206,
37.0597130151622,39.603384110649,42.1470525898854,44.6772511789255,47.2074392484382,
49.7375726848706,52.267704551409,54.7919476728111,57.3161862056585,59.840417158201,
62.364647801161,64.88673624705,67.4088226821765,69.9309084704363,72.4529952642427,
74.9756267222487,77.4982576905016,80.0208593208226,82.5434636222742,85.0694600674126,
87.5954571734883,90.1215846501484,92.6477183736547,95.1821827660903,97.7166481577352,
100.25062252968,102.784610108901,105.336431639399,107.88824952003,109.165248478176,
110.442175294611,111.719014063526,112.996131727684,115.598997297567,118.202030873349,
119.501050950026,120.799750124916,122.098534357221,123.397381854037,124.510975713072,
125.624581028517,126.73793945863,127.85130529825,128.967221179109,130.083174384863,
131.199120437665,131.757086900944,132.315052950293,132.702322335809,133.089593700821,
133.864380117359,134.251208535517,134.638011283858,135.024596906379,135.411130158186,
135.786611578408,136.162125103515,136.53702262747,136.91173305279,137.223943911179,
137.536111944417,137.847803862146,138.159510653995,138.469779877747,138.780081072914,
139.091053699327,139.40191165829,140.100140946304,140.799496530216,141.502359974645,
142.204786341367,142.917598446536,143.630494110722,144.341384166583,145.052273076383,
145.956073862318,146.8598711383,147.7636477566,148.667429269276,150.476097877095,
152.284826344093,154.079688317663,155.874577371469,157.669475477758,159.464222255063,
162.084383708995,164.703770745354,167.326947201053,169.95035310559,172.57558898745,
175.200778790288,177.82528765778,180.449764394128,183.013700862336,185.57759454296,
188.141406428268,190.705210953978,193.243693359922,195.782156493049,198.320572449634,
200.858985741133,203.38688715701,205.914780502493,208.442645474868,210.970509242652,
213.493804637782,216.017096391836,218.540382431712,221.063668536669,223.585653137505,
226.107636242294,228.629605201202,231.151575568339,233.674843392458,236.19811110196,
238.721416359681,241.244725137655,243.772615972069,246.300507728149,248.828288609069,
251.356076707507,253.894081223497,256.43208700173,258.970374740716,261.508680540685,
264.070989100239,266.633291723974,267.914401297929,269.195446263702,270.476410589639,
271.757626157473,273.072287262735,274.386963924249,275.701806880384,277.016530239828,
278.330430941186,279.644016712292,280.957588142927,282.271195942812,283.599080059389,
284.926795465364,285.591350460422,286.255906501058,286.920405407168,287.584903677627,
288.474432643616,288.919433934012,289.364424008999,289.808874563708,290.253289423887,
290.697335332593,291.141286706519,291.523128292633,291.905017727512,292.286054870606,
292.666889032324,292.979347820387,293.291758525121,293.603660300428,293.915601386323,
294.297165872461,294.678945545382,295.062610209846,295.446168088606,296.127169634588,
296.808859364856,297.492787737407,298.176440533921,298.864851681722,299.553316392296,
300.240504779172,300.927694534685,302.244597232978,303.561485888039,304.87898680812,
306.196436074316,307.509474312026,308.822509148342,310.135611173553,311.448802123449),.UNSPECIFIED.);
#1425=CARTESIAN_POINT('',(8.87764045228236,-4.5,16.8419191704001));
#1426=VERTEX_POINT('',#1425);
#1427=CARTESIAN_POINT('',(22.55548713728,-4.5,22.5));
#1428=VERTEX_POINT('',#1427);
#1429=EDGE_CURVE('E288',#1426,#1428,#1424,.T.);
#1430=ORIENTED_EDGE('',*,*,#1429,.T.);
#1431=CARTESIAN_POINT('',(11.6425345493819,-4.5,33.0180686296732));
#1432=CARTESIAN_POINT('',(11.8887940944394,-4.5,32.7883606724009));
#1433=CARTESIAN_POINT('',(12.1345901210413,-4.5,32.5581570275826));
#1434=CARTESIAN_POINT('',(12.625380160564,-4.5,32.0968979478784));
#1435=CARTESIAN_POINT('',(12.8703741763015,-4.5,31.8658425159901));
#1436=CARTESIAN_POINT('',(13.6043368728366,-4.5,31.1716115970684));
#1437=CARTESIAN_POINT('',(14.0922926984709,-4.5,30.7073654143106));
#1438=CARTESIAN_POINT('',(15.0661827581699,-4.5,29.7767913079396));
#1439=CARTESIAN_POINT('',(15.5521170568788,-4.5,29.3104634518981));
#1440=CARTESIAN_POINT('',(16.5224491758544,-4.5,28.3762088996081));
#1441=CARTESIAN_POINT('',(17.0068469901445,-4.5,27.9082821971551));
#1442=CARTESIAN_POINT('',(18.4582189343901,-4.5,26.5027042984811));
#1443=CARTESIAN_POINT('',(19.4234130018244,-4.5,25.5632155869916));
#1444=CARTESIAN_POINT('',(21.3507796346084,-4.5,23.6811286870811));
#1445=CARTESIAN_POINT('',(22.3129521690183,-4.5,22.7385304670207));
#1446=CARTESIAN_POINT('',(24.155145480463,-4.5,20.9298325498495));
#1447=CARTESIAN_POINT('',(25.0353323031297,-4.5,20.0639019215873));
#1448=CARTESIAN_POINT('',(26.7944244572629,-4.5,18.3307401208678));
#1449=CARTESIAN_POINT('',(27.6733297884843,-4.5,17.4635089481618));
#1450=CARTESIAN_POINT('',(30.3086128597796,-4.5,14.8603780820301));
#1451=CARTESIAN_POINT('',(32.0635642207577,-4.5,13.1230346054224));
#1452=CARTESIAN_POINT('',(35.5712829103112,-4.5,9.64594205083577));
#1453=CARTESIAN_POINT('',(37.3240501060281,-4.5,7.90619283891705));
#1454=CARTESIAN_POINT('',(39.9520670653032,-4.5,5.29542652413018));
#1455=CARTESIAN_POINT('',(40.8278840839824,-4.5,4.42498033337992));
#1456=CARTESIAN_POINT('',(42.5792011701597,-4.5,2.6837694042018));
#1457=CARTESIAN_POINT('',(43.4547012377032,-4.5,1.81300466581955));
#1458=CARTESIAN_POINT('',(44.3300735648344,-4.5,0.942111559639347));
#1459=B_SPLINE_CURVE_WITH_KNOTS('',3,(#1431,#1432,#1433,#1434,#1435,#1436,#1437,#1438,#1439,
#1440,#1441,#1442,#1443,#1444,#1445,#1446,#1447,#1448,#1449,#1450,#1451,#1452,#1453,#1454,#1455,
#1456,#1457,#1458),.UNSPECIFIED.,.F.,.F.,(4,2,2,2,2,2,2,2,2,2,2,2,2,4),(0.,1.01028789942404,
2.02057224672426,4.04111426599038,6.06159116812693,8.08207591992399,12.1228732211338,
16.1637117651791,19.8679078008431,23.572104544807,30.9804705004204,38.3892670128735,
42.0936681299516,45.7980687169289),.UNSPECIFIED.);
#1460=EDGE_CURVE('E307',#1428,#304,#1459,.T.);
#1461=ORIENTED_EDGE('',*,*,#1460,.T.);
#1462=ORIENTED_EDGE('',*,*,#320,.F.);
#1463=DIRECTION('',(-0.707106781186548,0.,0.707106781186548));
#1464=VECTOR('',#1463,1.);
#1465=CARTESIAN_POINT('',(35.5,-4.5,10.));
#1466=LINE('',#1465,#1464);
#1467=EDGE_CURVE('E388',#344,#312,#1466,.T.);
#1468=ORIENTED_EDGE('',*,*,#1467,.F.);
#1469=ORIENTED_EDGE('',*,*,#345,.F.);
#1470=ORIENTED_EDGE('',*,*,#270,.T.);
#1471=ORIENTED_EDGE('',*,*,#401,.T.);
#1472=DIRECTION('',(0.,0.,1.));
#1473=VECTOR('',#1472,1.);
#1474=CARTESIAN_POINT('',(8.87764045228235,-4.5,0.));
#1475=LINE('',#1474,#1473);
#1476=EDGE_CURVE('E421',#1426,#394,#1475,.T.);
#1477=ORIENTED_EDGE('',*,*,#1476,.F.);
#1478=EDGE_LOOP('',(#1430,#1461,#1462,#1468,#1469,#1470,#1471,#1477));
#1479=FACE_BOUND('',#1478,.T.);
#1480=ADVANCED_FACE('F163',(#1479),#1033,.F.);
#1481=CARTESIAN_POINT('',(8.87764045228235,-10.5,0.));
#1482=DIRECTION('',(0.,0.,1.));
#1483=DIRECTION('',(0.,-1.,0.));
#1484=AXIS2_PLACEMENT_3D('',#1481,#1482,#1483);
#1485=CYLINDRICAL_SURFACE('',#1484,6.);
#1486=CARTESIAN_POINT('',(5.00376098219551,-5.91818181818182,13.6426560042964));
#1487=CARTESIAN_POINT('',(5.0059161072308,-5.91635969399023,13.6453140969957));
#1488=CARTESIAN_POINT('',(5.00807252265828,-5.91453907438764,13.6479722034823));
#1489=CARTESIAN_POINT('',(5.15166899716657,-5.79347607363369,13.8248709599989));
#1490=CARTESIAN_POINT('',(5.29866177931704,-5.68069412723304,13.9991457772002));
#1491=CARTESIAN_POINT('',(5.60512104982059,-5.46755607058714,14.3446312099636));
#1492=CARTESIAN_POINT('',(5.76459853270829,-5.3672111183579,14.5158389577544));
#1493=CARTESIAN_POINT('',(6.09738136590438,-5.17960738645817,14.8511218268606));
#1494=CARTESIAN_POINT('',(6.27065600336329,-5.09232072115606,15.0152116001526));
#1495=CARTESIAN_POINT('',(6.6332433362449,-4.93206553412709,15.332036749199));
#1496=CARTESIAN_POINT('',(6.82252989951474,-4.85907430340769,15.4847898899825));
#1497=CARTESIAN_POINT('',(7.09690043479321,-4.76978611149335,15.6842480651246));
#1498=CARTESIAN_POINT('',(7.17434337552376,-4.74626344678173,15.7383131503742));
#1499=CARTESIAN_POINT('',(7.33200550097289,-4.70192108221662,15.8435010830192));
#1500=CARTESIAN_POINT('',(7.41222599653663,-4.68110268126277,15.8946225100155));
#1501=CARTESIAN_POINT('',(7.49386505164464,-4.66174977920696,15.9440475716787));
#1502=B_SPLINE_CURVE_WITH_KNOTS('',3,(#1486,#1487,#1488,#1489,#1490,#1491,#1492,#1493,#1494,
#1495,#1496,#1497,#1498,#1499,#1500,#1501),.UNSPECIFIED.,.F.,.F.,(4,2,2,2,2,2,2,4),(0.,
0.0116306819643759,0.774027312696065,1.53710306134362,2.29852527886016,3.05872795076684,
3.35062276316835,3.64265726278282),.UNSPECIFIED.);
#1503=CARTESIAN_POINT('',(7.49353468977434,-4.66182809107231,15.9438475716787));
#1504=VERTEX_POINT('',#1503);
#1505=EDGE_CURVE('E260',#433,#1504,#1502,.T.);
#1506=ORIENTED_EDGE('',*,*,#1505,.T.);
#1507=CARTESIAN_POINT('',(7.49320434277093,-4.66190641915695,15.9436475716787));
#1508=CARTESIAN_POINT('',(7.60943905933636,-4.63435875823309,16.0140509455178));
#1509=CARTESIAN_POINT('',(7.72548993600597,-4.61048878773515,16.0861329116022));
#1510=CARTESIAN_POINT('',(7.95693991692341,-4.56989665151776,16.2326288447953));
#1511=CARTESIAN_POINT('',(8.07233993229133,-4.55315590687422,16.3070362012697));
#1512=CARTESIAN_POINT('',(8.30280331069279,-4.52647413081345,16.457529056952));
#1513=CARTESIAN_POINT('',(8.41786670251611,-4.51653249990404,16.5336144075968));
#1514=CARTESIAN_POINT('',(8.64795886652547,-4.50329006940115,16.687069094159));
#1515=CARTESIAN_POINT('',(8.76298675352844,-4.50000678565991,16.7644412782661));
#1516=CARTESIAN_POINT('',(8.87784045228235,-4.50000000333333,16.8420543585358));
#1517=B_SPLINE_CURVE_WITH_KNOTS('',3,(#1507,#1508,#1509,#1510,#1511,#1512,#1513,#1514,#1515,
#1516),.UNSPECIFIED.,.F.,.F.,(4,2,2,2,4),(0.,0.415867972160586,0.830645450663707,
1.24538635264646,1.66121688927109),.UNSPECIFIED.);
#1518=EDGE_CURVE('E281',#1504,#1426,#1517,.T.);
#1519=ORIENTED_EDGE('',*,*,#1518,.T.);
#1520=ORIENTED_EDGE('',*,*,#1476,.T.);
#1521=ORIENTED_EDGE('',*,*,#395,.T.);
#1522=CARTESIAN_POINT('',(5.00376098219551,-5.91818181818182,26.7442638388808));
#1523=CARTESIAN_POINT('',(5.0185510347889,-5.90567678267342,26.7640009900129));
#1524=CARTESIAN_POINT('',(5.03308032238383,-5.89351543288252,26.784152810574));
#1525=CARTESIAN_POINT('',(5.06152881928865,-5.86992091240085,26.8252223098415));
#1526=CARTESIAN_POINT('',(5.07544919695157,-5.85848632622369,26.8461383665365));
#1527=CARTESIAN_POINT('',(5.10265156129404,-5.83633549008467,26.8887528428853));
#1528=CARTESIAN_POINT('',(5.11593353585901,-5.82561925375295,26.910451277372));
#1529=CARTESIAN_POINT('',(5.14182657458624,-5.80489933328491,26.9546446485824));
#1530=CARTESIAN_POINT('',(5.1544362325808,-5.79489712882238,26.9771411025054));
#1531=CARTESIAN_POINT('',(5.16666666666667,-5.78527057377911,27.));
#1532=B_SPLINE_CURVE_WITH_KNOTS('',3,(#1522,#1523,#1524,#1525,#1526,#1527,#1528,#1529,#1530,
#1531),.UNSPECIFIED.,.F.,.F.,(4,2,2,2,4),(0.,0.0829534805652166,0.165740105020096,
0.248528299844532,0.331483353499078),.UNSPECIFIED.);
#1533=EDGE_CURVE('E203',#441,#385,#1532,.T.);
#1534=ORIENTED_EDGE('',*,*,#1533,.F.);
#1535=ORIENTED_EDGE('',*,*,#442,.F.);
#1536=EDGE_LOOP('',(#1506,#1519,#1520,#1521,#1534,#1535));
#1537=FACE_BOUND('',#1536,.T.);
#1538=ADVANCED_FACE('F198',(#1537),#1485,.F.);
#1539=CARTESIAN_POINT('',(7.75,0.,6.));
#1540=DIRECTION('',(0.,0.,1.));
#1541=DIRECTION('',(0.,-1.,0.));
#1542=AXIS2_PLACEMENT_3D('',#1539,#1540,#1541);
#1543=PLANE('',#1542);
#1544=CARTESIAN_POINT('',(0.,0.,6.));
#1545=DIRECTION('',(0.,0.,-1.));
#1546=DIRECTION('',(0.,1.,0.));
#1547=AXIS2_PLACEMENT_3D('',#1544,#1545,#1546);
#1548=CIRCLE('',#1547,6.);
#1549=CARTESIAN_POINT('',(0.,6.,6.));
#1550=VERTEX_POINT('',#1549);
#1551=EDGE_CURVE('E375',#1550,#1550,#1548,.T.);
#1552=ORIENTED_EDGE('',*,*,#1551,.F.);
#1553=EDGE_LOOP('',(#1552));
#1554=FACE_BOUND('',#1553,.T.);
#1555=ORIENTED_EDGE('',*,*,#504,.T.);
#1556=EDGE_LOOP('',(#1555));
#1557=FACE_BOUND('',#1556,.T.);
#1558=ADVANCED_FACE('F353',(#1554,#1557),#1543,.F.);
#1559=CARTESIAN_POINT('',(0.,0.,0.));
#1560=DIRECTION('',(0.,0.,-1.));
#1561=DIRECTION('',(0.,1.,0.));
#1562=AXIS2_PLACEMENT_3D('',#1559,#1560,#1561);
#1563=CYLINDRICAL_SURFACE('',#1562,6.);
#1564=CARTESIAN_POINT('',(0.,0.,0.2));
#1565=DIRECTION('',(0.,0.,-1.));
#1566=DIRECTION('',(0.,1.,0.));
#1567=AXIS2_PLACEMENT_3D('',#1564,#1565,#1566);
#1568=CIRCLE('',#1567,6.);
#1569=CARTESIAN_POINT('',(0.,6.,0.2));
#1570=VERTEX_POINT('',#1569);
#1571=EDGE_CURVE('E380',#1570,#1570,#1568,.T.);
#1572=ORIENTED_EDGE('',*,*,#1571,.F.);
#1573=EDGE_LOOP('',(#1572));
#1574=FACE_BOUND('',#1573,.T.);
#1575=ORIENTED_EDGE('',*,*,#1551,.T.);
#1576=EDGE_LOOP('',(#1575));
#1577=FACE_BOUND('',#1576,.T.);
#1578=ADVANCED_FACE('F349',(#1574,#1577),#1563,.T.);
#1579=CARTESIAN_POINT('',(6.,0.,0.2));
#1580=DIRECTION('',(0.,0.,1.));
#1581=DIRECTION('',(0.,-1.,0.));
#1582=AXIS2_PLACEMENT_3D('',#1579,#1580,#1581);
#1583=PLANE('',#1582);
#1584=CARTESIAN_POINT('',(0.,0.,0.2));
#1585=DIRECTION('',(0.,0.,-1.));
#1586=DIRECTION('',(0.,1.,0.));
#1587=AXIS2_PLACEMENT_3D('',#1584,#1585,#1586);
#1588=CIRCLE('',#1587,4.8);
#1589=CARTESIAN_POINT('',(0.,4.8,0.2));
#1590=VERTEX_POINT('',#1589);
#1591=EDGE_CURVE('E430',#1590,#1590,#1588,.T.);
#1592=ORIENTED_EDGE('',*,*,#1591,.F.);
#1593=EDGE_LOOP('',(#1592));
#1594=FACE_BOUND('',#1593,.T.);
#1595=ORIENTED_EDGE('',*,*,#1571,.T.);
#1596=EDGE_LOOP('',(#1595));
#1597=FACE_BOUND('',#1596,.T.);
#1598=ADVANCED_FACE('F345',(#1594,#1597),#1583,.F.);
#1599=CARTESIAN_POINT('',(0.,0.,0.));
#1600=DIRECTION('',(0.,0.,-1.));
#1601=DIRECTION('',(0.,1.,0.));
#1602=AXIS2_PLACEMENT_3D('',#1599,#1600,#1601);
#1603=CYLINDRICAL_SURFACE('',#1602,4.8);
#1604=ORIENTED_EDGE('',*,*,#42,.F.);
#1605=EDGE_LOOP('',(#1604));
#1606=FACE_BOUND('',#1605,.T.);
#1607=ORIENTED_EDGE('',*,*,#1591,.T.);
#1608=EDGE_LOOP('',(#1607));
#1609=FACE_BOUND('',#1608,.T.);
#1610=ADVANCED_FACE('F324',(#1606,#1609),#1603,.T.);
#1611=EDGE_CURVE('E303',#587,#302,#300,.T.);
#1612=ORIENTED_EDGE('',*,*,#1611,.F.);
#1613=ORIENTED_EDGE('',*,*,#590,.T.);
#1614=EDGE_CURVE('E469',#302,#589,#310,.T.);
#1615=ORIENTED_EDGE('',*,*,#1614,.F.);
#1616=EDGE_LOOP('',(#1612,#1613,#1615));
#1617=FACE_BOUND('',#1616,.T.);
#1618=ADVANCED_FACE('F321',(#1617),#281,.F.);
#1619=CARTESIAN_POINT('',(25.,-9.,20.5));
#1620=DIRECTION('',(-0.707106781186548,0.,-0.707106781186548));
#1621=DIRECTION('',(0.707106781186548,0.,-0.707106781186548));
#1622=AXIS2_PLACEMENT_3D('',#1619,#1620,#1621);
#1623=PLANE('',#1622);
#1624=ORIENTED_EDGE('',*,*,#1024,.T.);
#1625=ORIENTED_EDGE('',*,*,#353,.F.);
#1626=ORIENTED_EDGE('',*,*,#1467,.T.);
#1627=ORIENTED_EDGE('',*,*,#313,.T.);
#1628=ORIENTED_EDGE('',*,*,#1614,.T.);
#1629=EDGE_LOOP('',(#1624,#1625,#1626,#1627,#1628));
#1630=FACE_BOUND('',#1629,.T.);
#1631=ADVANCED_FACE('F196',(#1630),#1623,.T.);
#1632=CARTESIAN_POINT('',(3.4032358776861,-9.,27.943563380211));
#1633=DIRECTION('',(0.,1.,0.));
#1634=DIRECTION('',(-1.,0.,0.));
#1635=AXIS2_PLACEMENT_3D('',#1632,#1633,#1634);
#1636=CYLINDRICAL_SURFACE('',#1635,1.99999999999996);
#1637=ORIENTED_EDGE('',*,*,#487,.T.);
#1638=ORIENTED_EDGE('',*,*,#67,.F.);
#1639=ORIENTED_EDGE('',*,*,#463,.T.);
#1640=ORIENTED_EDGE('',*,*,#1533,.T.);
#1641=ORIENTED_EDGE('',*,*,#386,.T.);
#1642=ORIENTED_EDGE('',*,*,#570,.T.);
#1643=EDGE_LOOP('',(#1637,#1638,#1639,#1640,#1641,#1642));
#1644=FACE_BOUND('',#1643,.T.);
#1645=ADVANCED_FACE('F189',(#1644),#1636,.F.);
#1646=CARTESIAN_POINT('',(29.,-9.,26.));
#1647=DIRECTION('',(0.,1.,0.));
#1648=DIRECTION('',(-1.,0.,0.));
#1649=AXIS2_PLACEMENT_3D('',#1646,#1647,#1648);
#1650=CYLINDRICAL_SURFACE('',#1649,1.);
#1651=ORIENTED_EDGE('',*,*,#258,.T.);
#1652=ORIENTED_EDGE('',*,*,#229,.T.);
#1653=ORIENTED_EDGE('',*,*,#408,.F.);
#1654=EDGE_LOOP('',(#1651,#1652,#1653));
#1655=FACE_BOUND('',#1654,.T.);
#1656=ADVANCED_FACE('F184',(#1655),#1650,.T.);
#1657=CARTESIAN_POINT('',(0.,0.,23.1));
#1658=DIRECTION('',(0.,0.,-1.));
#1659=DIRECTION('',(0.,1.,0.));
#1660=AXIS2_PLACEMENT_3D('',#1657,#1658,#1659);
#1661=TOROIDAL_SURFACE('',#1660,27.4,2.6);
#1662=ORIENTED_EDGE('',*,*,#174,.F.);
#1663=ORIENTED_EDGE('',*,*,#131,.F.);
#1664=ORIENTED_EDGE('',*,*,#336,.F.);
#1665=EDGE_LOOP('',(#1662,#1663,#1664));
#1666=FACE_BOUND('',#1665,.T.);
#1667=ADVANCED_FACE('F132',(#1666),#1661,.T.);
#1668=CARTESIAN_POINT('',(0.,0.,13.6426560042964));
#1669=DIRECTION('',(0.,0.,-1.));
#1670=DIRECTION('',(0.,1.,0.));
#1671=AXIS2_PLACEMENT_3D('',#1668,#1669,#1670);
#1672=TOROIDAL_SURFACE('',#1671,10.75,3.);
#1673=CARTESIAN_POINT('',(0.,0.,15.9438475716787));
#1674=DIRECTION('',(0.,0.,-1.));
#1675=DIRECTION('',(0.,1.,0.));
#1676=AXIS2_PLACEMENT_3D('',#1673,#1674,#1675);
#1677=CIRCLE('',#1676,8.82528771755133);
#1678=EDGE_CURVE('E475',#534,#1504,#1677,.T.);
#1679=ORIENTED_EDGE('',*,*,#1678,.T.);
#1680=ORIENTED_EDGE('',*,*,#1505,.F.);
#1681=ORIENTED_EDGE('',*,*,#434,.F.);
#1682=ORIENTED_EDGE('',*,*,#556,.F.);
#1683=EDGE_LOOP('',(#1679,#1680,#1681,#1682));
#1684=FACE_BOUND('',#1683,.T.);
#1685=ADVANCED_FACE('F274',(#1684),#1672,.F.);
#1686=CARTESIAN_POINT('',(0.,0.,-7.06806810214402));
#1687=DIRECTION('',(0.,0.,-1.));
#1688=DIRECTION('',(0.,1.,0.));
#1689=AXIS2_PLACEMENT_3D('',#1686,#1687,#1688);
#1690=DEGENERATE_TOROIDAL_SURFACE('',#1689,28.072410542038,30.,.T.);
#1691=ORIENTED_EDGE('',*,*,#1014,.F.);
#1692=CARTESIAN_POINT('',(0.,0.,22.5));
#1693=DIRECTION('',(0.,0.,-1.));
#1694=DIRECTION('',(0.,1.,0.));
#1695=AXIS2_PLACEMENT_3D('',#1692,#1693,#1694);
#1696=CIRCLE('',#1695,23.);
#1697=EDGE_CURVE('E29',#622,#302,#1696,.T.);
#1698=ORIENTED_EDGE('',*,*,#1697,.T.);
#1699=EDGE_CURVE('E476',#302,#1428,#1696,.T.);
#1700=ORIENTED_EDGE('',*,*,#1699,.T.);
#1701=ORIENTED_EDGE('',*,*,#1429,.F.);
#1702=ORIENTED_EDGE('',*,*,#1518,.F.);
#1703=ORIENTED_EDGE('',*,*,#1678,.F.);
#1704=ORIENTED_EDGE('',*,*,#535,.F.);
#1705=EDGE_LOOP('',(#1691,#1698,#1700,#1701,#1702,#1703,#1704));
#1706=FACE_BOUND('',#1705,.T.);
#1707=ADVANCED_FACE('F270',(#1706),#1690,.F.);
#1708=CARTESIAN_POINT('',(0.,0.,20.5));
#1709=DIRECTION('',(0.,0.,-1.));
#1710=DIRECTION('',(0.,1.,0.));
#1711=AXIS2_PLACEMENT_3D('',#1708,#1709,#1710);
#1712=CONICAL_SURFACE('',#1711,25.,0.785398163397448);
#1713=ORIENTED_EDGE('',*,*,#1611,.T.);
#1714=ORIENTED_EDGE('',*,*,#1697,.F.);
#1715=ORIENTED_EDGE('',*,*,#623,.F.);
#1716=EDGE_LOOP('',(#1713,#1714,#1715));
#1717=FACE_BOUND('',#1716,.T.);
#1718=ADVANCED_FACE('F273',(#1717),#1712,.F.);
#1719=ORIENTED_EDGE('',*,*,#1699,.F.);
#1720=ORIENTED_EDGE('',*,*,#305,.T.);
#1721=ORIENTED_EDGE('',*,*,#1460,.F.);
#1722=EDGE_LOOP('',(#1719,#1720,#1721));
#1723=FACE_BOUND('',#1722,.T.);
#1724=ADVANCED_FACE('F515',(#1723),#1712,.F.);
#1725=CARTESIAN_POINT('',(0.,0.,29.7));
#1726=DIRECTION('',(0.,0.,-1.));
#1727=DIRECTION('',(0.,1.,0.));
#1728=AXIS2_PLACEMENT_3D('',#1725,#1726,#1727);
#1729=PLANE('',#1728);
#1730=CARTESIAN_POINT('',(0.,0.,29.7));
#1731=DIRECTION('',(0.,0.,-1.));
#1732=DIRECTION('',(0.,1.,0.));
#1733=AXIS2_PLACEMENT_3D('',#1730,#1731,#1732);
#1734=CIRCLE('',#1733,2.69047619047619);
#1735=CARTESIAN_POINT('',(0.,2.69047619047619,29.7));
#1736=VERTEX_POINT('',#1735);
#1737=EDGE_CURVE('E481',#1736,#1736,#1734,.T.);
#1738=ORIENTED_EDGE('',*,*,#1737,.F.);
#1739=EDGE_LOOP('',(#1738));
#1740=FACE_BOUND('',#1739,.T.);
#1741=ADVANCED_FACE('F512',(#1740),#1729,.F.);
#1742=CARTESIAN_POINT('',(0.,0.,28.7));
#1743=DIRECTION('',(0.,0.,-1.));
#1744=DIRECTION('',(0.,1.,0.));
#1745=AXIS2_PLACEMENT_3D('',#1742,#1743,#1744);
#1746=TOROIDAL_SURFACE('',#1745,2.69047619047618,1.);
#1747=ORIENTED_EDGE('',*,*,#1737,.T.);
#1748=EDGE_LOOP('',(#1747));
#1749=FACE_BOUND('',#1748,.T.);
#1750=CARTESIAN_POINT('',(0.,0.,28.7));
#1751=DIRECTION('',(0.,0.,-1.));
#1752=DIRECTION('',(0.,1.,0.));
#1753=AXIS2_PLACEMENT_3D('',#1750,#1751,#1752);
#1754=CIRCLE('',#1753,3.69047619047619);
#1755=CARTESIAN_POINT('',(0.,3.69047619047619,28.7));
#1756=VERTEX_POINT('',#1755);
#1757=EDGE_CURVE('E484',#1756,#1756,#1754,.T.);
#1758=ORIENTED_EDGE('',*,*,#1757,.F.);
#1759=EDGE_LOOP('',(#1758));
#1760=FACE_BOUND('',#1759,.T.);
#1761=ADVANCED_FACE('F507',(#1749,#1760),#1746,.T.);
#1762=CARTESIAN_POINT('',(0.,0.,26.));
#1763=DIRECTION('',(0.,0.,-1.));
#1764=DIRECTION('',(0.,1.,0.));
#1765=AXIS2_PLACEMENT_3D('',#1762,#1763,#1764);
#1766=CYLINDRICAL_SURFACE('',#1765,3.69047619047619);
#1767=ORIENTED_EDGE('',*,*,#78,.T.);
#1768=EDGE_LOOP('',(#1767));
#1769=FACE_BOUND('',#1768,.T.);
#1770=ORIENTED_EDGE('',*,*,#1757,.T.);
#1771=EDGE_LOOP('',(#1770));
#1772=FACE_BOUND('',#1771,.T.);
#1773=ADVANCED_FACE('F499',(#1769,#1772),#1766,.T.);
#1774=CARTESIAN_POINT('',(0.,0.,10.));
#1775=DIRECTION('',(0.,0.,-1.));
#1776=DIRECTION('',(0.,1.,0.));
#1777=AXIS2_PLACEMENT_3D('',#1774,#1775,#1776);
#1778=CYLINDRICAL_SURFACE('',#1777,2.);
#1779=CARTESIAN_POINT('',(0.,0.,10.));
#1780=DIRECTION('',(0.,0.,-1.));
#1781=DIRECTION('',(0.,1.,0.));
#1782=AXIS2_PLACEMENT_3D('',#1779,#1780,#1781);
#1783=CIRCLE('',#1782,2.);
#1784=CARTESIAN_POINT('',(0.,2.,10.));
#1785=VERTEX_POINT('',#1784);
#1786=EDGE_CURVE('E487',#1785,#1785,#1783,.T.);
#1787=ORIENTED_EDGE('',*,*,#1786,.F.);
#1788=EDGE_LOOP('',(#1787));
#1789=FACE_BOUND('',#1788,.T.);
#1790=ORIENTED_EDGE('',*,*,#31,.T.);
#1791=EDGE_LOOP('',(#1790));
#1792=FACE_BOUND('',#1791,.T.);
#1793=ADVANCED_FACE('F496',(#1789,#1792),#1778,.F.);
#1794=CARTESIAN_POINT('',(0.,0.,10.));
#1795=DIRECTION('',(0.,0.,-1.));
#1796=DIRECTION('',(0.,1.,0.));
#1797=AXIS2_PLACEMENT_3D('',#1794,#1795,#1796);
#1798=PLANE('',#1797);
#1799=ORIENTED_EDGE('',*,*,#1786,.T.);
#1800=EDGE_LOOP('',(#1799));
#1801=FACE_BOUND('',#1800,.T.);
#1802=ADVANCED_FACE('F494',(#1801),#1798,.T.);
#1803=CLOSED_SHELL('',(#46,#82,#276,#324,#363,#419,#508,#575,#1028,#1480,#1538,#1558,#1578,
#1598,#1610,#1618,#1631,#1645,#1656,#1667,#1685,#1707,#1718,#1724,#1741,#1761,#1773,#1793,#1802));
#1804=MANIFOLD_SOLID_BREP('B1',#1803);
#1805=ADVANCED_BREP_SHAPE_REPRESENTATION('',(#18,#1804),#14);
#1806=SHAPE_DEFINITION_REPRESENTATION(#9,#1805);
ENDSEC;
END-ISO-10303-21;
